VERSION 5.8 ;
BUSBITCHARS "[]" ;
DIVIDERCHAR "/" ;
UNITS
    DATABASE MICRONS 1000 ;
END UNITS

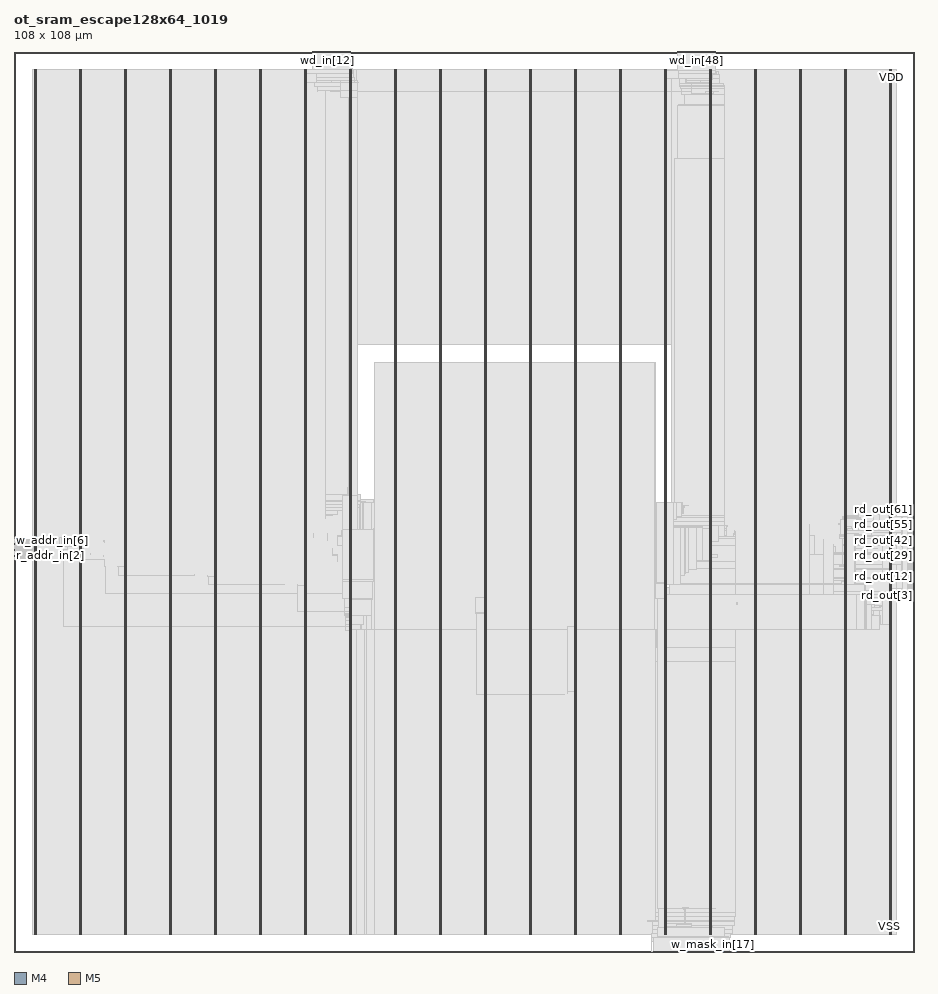
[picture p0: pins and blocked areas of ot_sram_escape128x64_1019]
MACRO ot_sram_escape128x64_1019
  FOREIGN ot_sram_escape128x64_1019 0 0 ;
  CLASS BLOCK ;
  SIZE 108 BY 108 ;
  PIN clk
    DIRECTION INPUT ;
    USE SIGNAL ;
    PORT
      LAYER M4 ;
        RECT  0 47.088 0.084 47.112 ;
    END
  END clk
  PIN r_addr_in[0]
    DIRECTION INPUT ;
    USE SIGNAL ;
    PORT
      LAYER M4 ;
        RECT  0 47.232 0.084 47.256 ;
    END
  END r_addr_in[0]
  PIN r_addr_in[1]
    DIRECTION INPUT ;
    USE SIGNAL ;
    PORT
      LAYER M4 ;
        RECT  0 47.376 0.084 47.4 ;
    END
  END r_addr_in[1]
  PIN r_addr_in[2]
    DIRECTION INPUT ;
    USE SIGNAL ;
    PORT
      LAYER M4 ;
        RECT  0 47.52 0.084 47.544 ;
    END
  END r_addr_in[2]
  PIN r_addr_in[3]
    DIRECTION INPUT ;
    USE SIGNAL ;
    PORT
      LAYER M4 ;
        RECT  0 47.664 0.084 47.688 ;
    END
  END r_addr_in[3]
  PIN r_addr_in[4]
    DIRECTION INPUT ;
    USE SIGNAL ;
    PORT
      LAYER M4 ;
        RECT  0 47.808 0.084 47.832 ;
    END
  END r_addr_in[4]
  PIN r_addr_in[5]
    DIRECTION INPUT ;
    USE SIGNAL ;
    PORT
      LAYER M4 ;
        RECT  0 47.952 0.084 47.976 ;
    END
  END r_addr_in[5]
  PIN r_addr_in[6]
    DIRECTION INPUT ;
    USE SIGNAL ;
    PORT
      LAYER M4 ;
        RECT  0 48.096 0.084 48.12 ;
    END
  END r_addr_in[6]
  PIN r_ce_in
    DIRECTION INPUT ;
    USE SIGNAL ;
    PORT
      LAYER M4 ;
        RECT  0 48.24 0.084 48.264 ;
    END
  END r_ce_in
  PIN rd_out[0]
    DIRECTION OUTPUT ;
    USE SIGNAL ;
    PORT
      LAYER M4 ;
        RECT  107.916 43.344 108 43.368 ;
    END
  END rd_out[0]
  PIN rd_out[10]
    DIRECTION OUTPUT ;
    USE SIGNAL ;
    PORT
      LAYER M4 ;
        RECT  107.916 44.784 108 44.808 ;
    END
  END rd_out[10]
  PIN rd_out[11]
    DIRECTION OUTPUT ;
    USE SIGNAL ;
    PORT
      LAYER M4 ;
        RECT  107.916 44.928 108 44.952 ;
    END
  END rd_out[11]
  PIN rd_out[12]
    DIRECTION OUTPUT ;
    USE SIGNAL ;
    PORT
      LAYER M4 ;
        RECT  107.916 45.072 108 45.096 ;
    END
  END rd_out[12]
  PIN rd_out[13]
    DIRECTION OUTPUT ;
    USE SIGNAL ;
    PORT
      LAYER M4 ;
        RECT  107.916 45.216 108 45.24 ;
    END
  END rd_out[13]
  PIN rd_out[14]
    DIRECTION OUTPUT ;
    USE SIGNAL ;
    PORT
      LAYER M4 ;
        RECT  107.916 45.36 108 45.384 ;
    END
  END rd_out[14]
  PIN rd_out[15]
    DIRECTION OUTPUT ;
    USE SIGNAL ;
    PORT
      LAYER M4 ;
        RECT  107.916 45.504 108 45.528 ;
    END
  END rd_out[15]
  PIN rd_out[16]
    DIRECTION OUTPUT ;
    USE SIGNAL ;
    PORT
      LAYER M4 ;
        RECT  107.916 45.648 108 45.672 ;
    END
  END rd_out[16]
  PIN rd_out[17]
    DIRECTION OUTPUT ;
    USE SIGNAL ;
    PORT
      LAYER M4 ;
        RECT  107.916 45.792 108 45.816 ;
    END
  END rd_out[17]
  PIN rd_out[18]
    DIRECTION OUTPUT ;
    USE SIGNAL ;
    PORT
      LAYER M4 ;
        RECT  107.916 45.936 108 45.96 ;
    END
  END rd_out[18]
  PIN rd_out[19]
    DIRECTION OUTPUT ;
    USE SIGNAL ;
    PORT
      LAYER M4 ;
        RECT  107.916 46.08 108 46.104 ;
    END
  END rd_out[19]
  PIN rd_out[1]
    DIRECTION OUTPUT ;
    USE SIGNAL ;
    PORT
      LAYER M4 ;
        RECT  107.916 43.488 108 43.512 ;
    END
  END rd_out[1]
  PIN rd_out[20]
    DIRECTION OUTPUT ;
    USE SIGNAL ;
    PORT
      LAYER M4 ;
        RECT  107.916 46.224 108 46.248 ;
    END
  END rd_out[20]
  PIN rd_out[21]
    DIRECTION OUTPUT ;
    USE SIGNAL ;
    PORT
      LAYER M4 ;
        RECT  107.916 46.368 108 46.392 ;
    END
  END rd_out[21]
  PIN rd_out[22]
    DIRECTION OUTPUT ;
    USE SIGNAL ;
    PORT
      LAYER M4 ;
        RECT  107.916 46.512 108 46.536 ;
    END
  END rd_out[22]
  PIN rd_out[23]
    DIRECTION OUTPUT ;
    USE SIGNAL ;
    PORT
      LAYER M4 ;
        RECT  107.916 46.656 108 46.68 ;
    END
  END rd_out[23]
  PIN rd_out[24]
    DIRECTION OUTPUT ;
    USE SIGNAL ;
    PORT
      LAYER M4 ;
        RECT  107.916 46.8 108 46.824 ;
    END
  END rd_out[24]
  PIN rd_out[25]
    DIRECTION OUTPUT ;
    USE SIGNAL ;
    PORT
      LAYER M4 ;
        RECT  107.916 46.944 108 46.968 ;
    END
  END rd_out[25]
  PIN rd_out[26]
    DIRECTION OUTPUT ;
    USE SIGNAL ;
    PORT
      LAYER M4 ;
        RECT  107.916 47.088 108 47.112 ;
    END
  END rd_out[26]
  PIN rd_out[27]
    DIRECTION OUTPUT ;
    USE SIGNAL ;
    PORT
      LAYER M4 ;
        RECT  107.916 47.232 108 47.256 ;
    END
  END rd_out[27]
  PIN rd_out[28]
    DIRECTION OUTPUT ;
    USE SIGNAL ;
    PORT
      LAYER M4 ;
        RECT  107.916 47.376 108 47.4 ;
    END
  END rd_out[28]
  PIN rd_out[29]
    DIRECTION OUTPUT ;
    USE SIGNAL ;
    PORT
      LAYER M4 ;
        RECT  107.916 47.52 108 47.544 ;
    END
  END rd_out[29]
  PIN rd_out[2]
    DIRECTION OUTPUT ;
    USE SIGNAL ;
    PORT
      LAYER M4 ;
        RECT  107.916 43.632 108 43.656 ;
    END
  END rd_out[2]
  PIN rd_out[30]
    DIRECTION OUTPUT ;
    USE SIGNAL ;
    PORT
      LAYER M4 ;
        RECT  107.916 47.664 108 47.688 ;
    END
  END rd_out[30]
  PIN rd_out[31]
    DIRECTION OUTPUT ;
    USE SIGNAL ;
    PORT
      LAYER M4 ;
        RECT  107.916 47.808 108 47.832 ;
    END
  END rd_out[31]
  PIN rd_out[32]
    DIRECTION OUTPUT ;
    USE SIGNAL ;
    PORT
      LAYER M4 ;
        RECT  107.916 47.952 108 47.976 ;
    END
  END rd_out[32]
  PIN rd_out[33]
    DIRECTION OUTPUT ;
    USE SIGNAL ;
    PORT
      LAYER M4 ;
        RECT  107.916 48.096 108 48.12 ;
    END
  END rd_out[33]
  PIN rd_out[34]
    DIRECTION OUTPUT ;
    USE SIGNAL ;
    PORT
      LAYER M4 ;
        RECT  107.916 48.24 108 48.264 ;
    END
  END rd_out[34]
  PIN rd_out[35]
    DIRECTION OUTPUT ;
    USE SIGNAL ;
    PORT
      LAYER M4 ;
        RECT  107.916 48.384 108 48.408 ;
    END
  END rd_out[35]
  PIN rd_out[36]
    DIRECTION OUTPUT ;
    USE SIGNAL ;
    PORT
      LAYER M4 ;
        RECT  107.916 48.528 108 48.552 ;
    END
  END rd_out[36]
  PIN rd_out[37]
    DIRECTION OUTPUT ;
    USE SIGNAL ;
    PORT
      LAYER M4 ;
        RECT  107.916 48.672 108 48.696 ;
    END
  END rd_out[37]
  PIN rd_out[38]
    DIRECTION OUTPUT ;
    USE SIGNAL ;
    PORT
      LAYER M4 ;
        RECT  107.916 48.816 108 48.84 ;
    END
  END rd_out[38]
  PIN rd_out[39]
    DIRECTION OUTPUT ;
    USE SIGNAL ;
    PORT
      LAYER M4 ;
        RECT  107.916 48.96 108 48.984 ;
    END
  END rd_out[39]
  PIN rd_out[3]
    DIRECTION OUTPUT ;
    USE SIGNAL ;
    PORT
      LAYER M4 ;
        RECT  107.916 43.776 108 43.8 ;
    END
  END rd_out[3]
  PIN rd_out[40]
    DIRECTION OUTPUT ;
    USE SIGNAL ;
    PORT
      LAYER M4 ;
        RECT  107.916 49.104 108 49.128 ;
    END
  END rd_out[40]
  PIN rd_out[41]
    DIRECTION OUTPUT ;
    USE SIGNAL ;
    PORT
      LAYER M4 ;
        RECT  107.916 49.248 108 49.272 ;
    END
  END rd_out[41]
  PIN rd_out[42]
    DIRECTION OUTPUT ;
    USE SIGNAL ;
    PORT
      LAYER M4 ;
        RECT  107.916 49.392 108 49.416 ;
    END
  END rd_out[42]
  PIN rd_out[43]
    DIRECTION OUTPUT ;
    USE SIGNAL ;
    PORT
      LAYER M4 ;
        RECT  107.916 49.536 108 49.56 ;
    END
  END rd_out[43]
  PIN rd_out[44]
    DIRECTION OUTPUT ;
    USE SIGNAL ;
    PORT
      LAYER M4 ;
        RECT  107.916 49.68 108 49.704 ;
    END
  END rd_out[44]
  PIN rd_out[45]
    DIRECTION OUTPUT ;
    USE SIGNAL ;
    PORT
      LAYER M4 ;
        RECT  107.916 49.824 108 49.848 ;
    END
  END rd_out[45]
  PIN rd_out[46]
    DIRECTION OUTPUT ;
    USE SIGNAL ;
    PORT
      LAYER M4 ;
        RECT  107.916 49.968 108 49.992 ;
    END
  END rd_out[46]
  PIN rd_out[47]
    DIRECTION OUTPUT ;
    USE SIGNAL ;
    PORT
      LAYER M4 ;
        RECT  107.916 50.112 108 50.136 ;
    END
  END rd_out[47]
  PIN rd_out[48]
    DIRECTION OUTPUT ;
    USE SIGNAL ;
    PORT
      LAYER M4 ;
        RECT  107.916 50.256 108 50.28 ;
    END
  END rd_out[48]
  PIN rd_out[49]
    DIRECTION OUTPUT ;
    USE SIGNAL ;
    PORT
      LAYER M4 ;
        RECT  107.916 50.4 108 50.424 ;
    END
  END rd_out[49]
  PIN rd_out[4]
    DIRECTION OUTPUT ;
    USE SIGNAL ;
    PORT
      LAYER M4 ;
        RECT  107.916 43.92 108 43.944 ;
    END
  END rd_out[4]
  PIN rd_out[50]
    DIRECTION OUTPUT ;
    USE SIGNAL ;
    PORT
      LAYER M4 ;
        RECT  107.916 50.544 108 50.568 ;
    END
  END rd_out[50]
  PIN rd_out[51]
    DIRECTION OUTPUT ;
    USE SIGNAL ;
    PORT
      LAYER M4 ;
        RECT  107.916 50.688 108 50.712 ;
    END
  END rd_out[51]
  PIN rd_out[52]
    DIRECTION OUTPUT ;
    USE SIGNAL ;
    PORT
      LAYER M4 ;
        RECT  107.916 50.832 108 50.856 ;
    END
  END rd_out[52]
  PIN rd_out[53]
    DIRECTION OUTPUT ;
    USE SIGNAL ;
    PORT
      LAYER M4 ;
        RECT  107.916 50.976 108 51 ;
    END
  END rd_out[53]
  PIN rd_out[54]
    DIRECTION OUTPUT ;
    USE SIGNAL ;
    PORT
      LAYER M4 ;
        RECT  107.916 51.12 108 51.144 ;
    END
  END rd_out[54]
  PIN rd_out[55]
    DIRECTION OUTPUT ;
    USE SIGNAL ;
    PORT
      LAYER M4 ;
        RECT  107.916 51.264 108 51.288 ;
    END
  END rd_out[55]
  PIN rd_out[56]
    DIRECTION OUTPUT ;
    USE SIGNAL ;
    PORT
      LAYER M4 ;
        RECT  107.916 51.408 108 51.432 ;
    END
  END rd_out[56]
  PIN rd_out[57]
    DIRECTION OUTPUT ;
    USE SIGNAL ;
    PORT
      LAYER M4 ;
        RECT  107.916 51.552 108 51.576 ;
    END
  END rd_out[57]
  PIN rd_out[58]
    DIRECTION OUTPUT ;
    USE SIGNAL ;
    PORT
      LAYER M4 ;
        RECT  107.916 51.696 108 51.72 ;
    END
  END rd_out[58]
  PIN rd_out[59]
    DIRECTION OUTPUT ;
    USE SIGNAL ;
    PORT
      LAYER M4 ;
        RECT  107.916 51.84 108 51.864 ;
    END
  END rd_out[59]
  PIN rd_out[5]
    DIRECTION OUTPUT ;
    USE SIGNAL ;
    PORT
      LAYER M4 ;
        RECT  107.916 44.064 108 44.088 ;
    END
  END rd_out[5]
  PIN rd_out[60]
    DIRECTION OUTPUT ;
    USE SIGNAL ;
    PORT
      LAYER M4 ;
        RECT  107.916 51.984 108 52.008 ;
    END
  END rd_out[60]
  PIN rd_out[61]
    DIRECTION OUTPUT ;
    USE SIGNAL ;
    PORT
      LAYER M4 ;
        RECT  107.916 52.128 108 52.152 ;
    END
  END rd_out[61]
  PIN rd_out[62]
    DIRECTION OUTPUT ;
    USE SIGNAL ;
    PORT
      LAYER M4 ;
        RECT  107.916 52.272 108 52.296 ;
    END
  END rd_out[62]
  PIN rd_out[63]
    DIRECTION OUTPUT ;
    USE SIGNAL ;
    PORT
      LAYER M4 ;
        RECT  107.916 52.416 108 52.44 ;
    END
  END rd_out[63]
  PIN rd_out[6]
    DIRECTION OUTPUT ;
    USE SIGNAL ;
    PORT
      LAYER M4 ;
        RECT  107.916 44.208 108 44.232 ;
    END
  END rd_out[6]
  PIN rd_out[7]
    DIRECTION OUTPUT ;
    USE SIGNAL ;
    PORT
      LAYER M4 ;
        RECT  107.916 44.352 108 44.376 ;
    END
  END rd_out[7]
  PIN rd_out[8]
    DIRECTION OUTPUT ;
    USE SIGNAL ;
    PORT
      LAYER M4 ;
        RECT  107.916 44.496 108 44.52 ;
    END
  END rd_out[8]
  PIN rd_out[9]
    DIRECTION OUTPUT ;
    USE SIGNAL ;
    PORT
      LAYER M4 ;
        RECT  107.916 44.64 108 44.664 ;
    END
  END rd_out[9]
  PIN rst_n
    DIRECTION INPUT ;
    USE SIGNAL ;
    PORT
      LAYER M4 ;
        RECT  0 48.384 0.084 48.408 ;
    END
  END rst_n
  PIN w_addr_in[0]
    DIRECTION INPUT ;
    USE SIGNAL ;
    PORT
      LAYER M4 ;
        RECT  0 48.528 0.084 48.552 ;
    END
  END w_addr_in[0]
  PIN w_addr_in[1]
    DIRECTION INPUT ;
    USE SIGNAL ;
    PORT
      LAYER M4 ;
        RECT  0 48.672 0.084 48.696 ;
    END
  END w_addr_in[1]
  PIN w_addr_in[2]
    DIRECTION INPUT ;
    USE SIGNAL ;
    PORT
      LAYER M4 ;
        RECT  0 48.816 0.084 48.84 ;
    END
  END w_addr_in[2]
  PIN w_addr_in[3]
    DIRECTION INPUT ;
    USE SIGNAL ;
    PORT
      LAYER M4 ;
        RECT  0 48.96 0.084 48.984 ;
    END
  END w_addr_in[3]
  PIN w_addr_in[4]
    DIRECTION INPUT ;
    USE SIGNAL ;
    PORT
      LAYER M4 ;
        RECT  0 49.104 0.084 49.128 ;
    END
  END w_addr_in[4]
  PIN w_addr_in[5]
    DIRECTION INPUT ;
    USE SIGNAL ;
    PORT
      LAYER M4 ;
        RECT  0 49.248 0.084 49.272 ;
    END
  END w_addr_in[5]
  PIN w_addr_in[6]
    DIRECTION INPUT ;
    USE SIGNAL ;
    PORT
      LAYER M4 ;
        RECT  0 49.392 0.084 49.416 ;
    END
  END w_addr_in[6]
  PIN w_ce_in
    DIRECTION INPUT ;
    USE SIGNAL ;
    PORT
      LAYER M4 ;
        RECT  0 49.536 0.084 49.56 ;
    END
  END w_ce_in
  PIN w_mask_in[0]
    DIRECTION INPUT ;
    USE SIGNAL ;
    PORT
      LAYER M5 ;
        RECT  81.36 0 81.384 0.084 ;
    END
  END w_mask_in[0]
  PIN w_mask_in[10]
    DIRECTION INPUT ;
    USE SIGNAL ;
    PORT
      LAYER M5 ;
        RECT  82.8 0 82.824 0.084 ;
    END
  END w_mask_in[10]
  PIN w_mask_in[11]
    DIRECTION INPUT ;
    USE SIGNAL ;
    PORT
      LAYER M5 ;
        RECT  82.944 0 82.968 0.084 ;
    END
  END w_mask_in[11]
  PIN w_mask_in[12]
    DIRECTION INPUT ;
    USE SIGNAL ;
    PORT
      LAYER M5 ;
        RECT  83.088 0 83.112 0.084 ;
    END
  END w_mask_in[12]
  PIN w_mask_in[13]
    DIRECTION INPUT ;
    USE SIGNAL ;
    PORT
      LAYER M5 ;
        RECT  83.232 0 83.256 0.084 ;
    END
  END w_mask_in[13]
  PIN w_mask_in[14]
    DIRECTION INPUT ;
    USE SIGNAL ;
    PORT
      LAYER M5 ;
        RECT  83.376 0 83.4 0.084 ;
    END
  END w_mask_in[14]
  PIN w_mask_in[15]
    DIRECTION INPUT ;
    USE SIGNAL ;
    PORT
      LAYER M5 ;
        RECT  83.52 0 83.544 0.084 ;
    END
  END w_mask_in[15]
  PIN w_mask_in[16]
    DIRECTION INPUT ;
    USE SIGNAL ;
    PORT
      LAYER M5 ;
        RECT  83.664 0 83.688 0.084 ;
    END
  END w_mask_in[16]
  PIN w_mask_in[17]
    DIRECTION INPUT ;
    USE SIGNAL ;
    PORT
      LAYER M5 ;
        RECT  83.808 0 83.832 0.084 ;
    END
  END w_mask_in[17]
  PIN w_mask_in[18]
    DIRECTION INPUT ;
    USE SIGNAL ;
    PORT
      LAYER M5 ;
        RECT  83.952 0 83.976 0.084 ;
    END
  END w_mask_in[18]
  PIN w_mask_in[19]
    DIRECTION INPUT ;
    USE SIGNAL ;
    PORT
      LAYER M5 ;
        RECT  84.096 0 84.12 0.084 ;
    END
  END w_mask_in[19]
  PIN w_mask_in[1]
    DIRECTION INPUT ;
    USE SIGNAL ;
    PORT
      LAYER M5 ;
        RECT  81.504 0 81.528 0.084 ;
    END
  END w_mask_in[1]
  PIN w_mask_in[20]
    DIRECTION INPUT ;
    USE SIGNAL ;
    PORT
      LAYER M5 ;
        RECT  84.24 0 84.264 0.084 ;
    END
  END w_mask_in[20]
  PIN w_mask_in[21]
    DIRECTION INPUT ;
    USE SIGNAL ;
    PORT
      LAYER M5 ;
        RECT  84.384 0 84.408 0.084 ;
    END
  END w_mask_in[21]
  PIN w_mask_in[22]
    DIRECTION INPUT ;
    USE SIGNAL ;
    PORT
      LAYER M5 ;
        RECT  84.528 0 84.552 0.084 ;
    END
  END w_mask_in[22]
  PIN w_mask_in[23]
    DIRECTION INPUT ;
    USE SIGNAL ;
    PORT
      LAYER M5 ;
        RECT  84.672 0 84.696 0.084 ;
    END
  END w_mask_in[23]
  PIN w_mask_in[24]
    DIRECTION INPUT ;
    USE SIGNAL ;
    PORT
      LAYER M5 ;
        RECT  84.816 0 84.84 0.084 ;
    END
  END w_mask_in[24]
  PIN w_mask_in[25]
    DIRECTION INPUT ;
    USE SIGNAL ;
    PORT
      LAYER M5 ;
        RECT  84.96 0 84.984 0.084 ;
    END
  END w_mask_in[25]
  PIN w_mask_in[26]
    DIRECTION INPUT ;
    USE SIGNAL ;
    PORT
      LAYER M5 ;
        RECT  85.104 0 85.128 0.084 ;
    END
  END w_mask_in[26]
  PIN w_mask_in[27]
    DIRECTION INPUT ;
    USE SIGNAL ;
    PORT
      LAYER M5 ;
        RECT  85.248 0 85.272 0.084 ;
    END
  END w_mask_in[27]
  PIN w_mask_in[28]
    DIRECTION INPUT ;
    USE SIGNAL ;
    PORT
      LAYER M5 ;
        RECT  85.392 0 85.416 0.084 ;
    END
  END w_mask_in[28]
  PIN w_mask_in[29]
    DIRECTION INPUT ;
    USE SIGNAL ;
    PORT
      LAYER M5 ;
        RECT  85.536 0 85.56 0.084 ;
    END
  END w_mask_in[29]
  PIN w_mask_in[2]
    DIRECTION INPUT ;
    USE SIGNAL ;
    PORT
      LAYER M5 ;
        RECT  81.648 0 81.672 0.084 ;
    END
  END w_mask_in[2]
  PIN w_mask_in[30]
    DIRECTION INPUT ;
    USE SIGNAL ;
    PORT
      LAYER M5 ;
        RECT  85.68 0 85.704 0.084 ;
    END
  END w_mask_in[30]
  PIN w_mask_in[31]
    DIRECTION INPUT ;
    USE SIGNAL ;
    PORT
      LAYER M5 ;
        RECT  85.824 0 85.848 0.084 ;
    END
  END w_mask_in[31]
  PIN w_mask_in[32]
    DIRECTION INPUT ;
    USE SIGNAL ;
    PORT
      LAYER M5 ;
        RECT  76.752 0 76.776 0.084 ;
    END
  END w_mask_in[32]
  PIN w_mask_in[33]
    DIRECTION INPUT ;
    USE SIGNAL ;
    PORT
      LAYER M5 ;
        RECT  76.896 0 76.92 0.084 ;
    END
  END w_mask_in[33]
  PIN w_mask_in[34]
    DIRECTION INPUT ;
    USE SIGNAL ;
    PORT
      LAYER M5 ;
        RECT  77.04 0 77.064 0.084 ;
    END
  END w_mask_in[34]
  PIN w_mask_in[35]
    DIRECTION INPUT ;
    USE SIGNAL ;
    PORT
      LAYER M5 ;
        RECT  77.184 0 77.208 0.084 ;
    END
  END w_mask_in[35]
  PIN w_mask_in[36]
    DIRECTION INPUT ;
    USE SIGNAL ;
    PORT
      LAYER M5 ;
        RECT  77.328 0 77.352 0.084 ;
    END
  END w_mask_in[36]
  PIN w_mask_in[37]
    DIRECTION INPUT ;
    USE SIGNAL ;
    PORT
      LAYER M5 ;
        RECT  77.472 0 77.496 0.084 ;
    END
  END w_mask_in[37]
  PIN w_mask_in[38]
    DIRECTION INPUT ;
    USE SIGNAL ;
    PORT
      LAYER M5 ;
        RECT  77.616 0 77.64 0.084 ;
    END
  END w_mask_in[38]
  PIN w_mask_in[39]
    DIRECTION INPUT ;
    USE SIGNAL ;
    PORT
      LAYER M5 ;
        RECT  77.76 0 77.784 0.084 ;
    END
  END w_mask_in[39]
  PIN w_mask_in[3]
    DIRECTION INPUT ;
    USE SIGNAL ;
    PORT
      LAYER M5 ;
        RECT  81.792 0 81.816 0.084 ;
    END
  END w_mask_in[3]
  PIN w_mask_in[40]
    DIRECTION INPUT ;
    USE SIGNAL ;
    PORT
      LAYER M5 ;
        RECT  77.904 0 77.928 0.084 ;
    END
  END w_mask_in[40]
  PIN w_mask_in[41]
    DIRECTION INPUT ;
    USE SIGNAL ;
    PORT
      LAYER M5 ;
        RECT  78.048 0 78.072 0.084 ;
    END
  END w_mask_in[41]
  PIN w_mask_in[42]
    DIRECTION INPUT ;
    USE SIGNAL ;
    PORT
      LAYER M5 ;
        RECT  78.192 0 78.216 0.084 ;
    END
  END w_mask_in[42]
  PIN w_mask_in[43]
    DIRECTION INPUT ;
    USE SIGNAL ;
    PORT
      LAYER M5 ;
        RECT  78.336 0 78.36 0.084 ;
    END
  END w_mask_in[43]
  PIN w_mask_in[44]
    DIRECTION INPUT ;
    USE SIGNAL ;
    PORT
      LAYER M5 ;
        RECT  78.48 0 78.504 0.084 ;
    END
  END w_mask_in[44]
  PIN w_mask_in[45]
    DIRECTION INPUT ;
    USE SIGNAL ;
    PORT
      LAYER M5 ;
        RECT  78.624 0 78.648 0.084 ;
    END
  END w_mask_in[45]
  PIN w_mask_in[46]
    DIRECTION INPUT ;
    USE SIGNAL ;
    PORT
      LAYER M5 ;
        RECT  78.768 0 78.792 0.084 ;
    END
  END w_mask_in[46]
  PIN w_mask_in[47]
    DIRECTION INPUT ;
    USE SIGNAL ;
    PORT
      LAYER M5 ;
        RECT  78.912 0 78.936 0.084 ;
    END
  END w_mask_in[47]
  PIN w_mask_in[48]
    DIRECTION INPUT ;
    USE SIGNAL ;
    PORT
      LAYER M5 ;
        RECT  79.056 0 79.08 0.084 ;
    END
  END w_mask_in[48]
  PIN w_mask_in[49]
    DIRECTION INPUT ;
    USE SIGNAL ;
    PORT
      LAYER M5 ;
        RECT  79.2 0 79.224 0.084 ;
    END
  END w_mask_in[49]
  PIN w_mask_in[4]
    DIRECTION INPUT ;
    USE SIGNAL ;
    PORT
      LAYER M5 ;
        RECT  81.936 0 81.96 0.084 ;
    END
  END w_mask_in[4]
  PIN w_mask_in[50]
    DIRECTION INPUT ;
    USE SIGNAL ;
    PORT
      LAYER M5 ;
        RECT  79.344 0 79.368 0.084 ;
    END
  END w_mask_in[50]
  PIN w_mask_in[51]
    DIRECTION INPUT ;
    USE SIGNAL ;
    PORT
      LAYER M5 ;
        RECT  79.488 0 79.512 0.084 ;
    END
  END w_mask_in[51]
  PIN w_mask_in[52]
    DIRECTION INPUT ;
    USE SIGNAL ;
    PORT
      LAYER M5 ;
        RECT  79.632 0 79.656 0.084 ;
    END
  END w_mask_in[52]
  PIN w_mask_in[53]
    DIRECTION INPUT ;
    USE SIGNAL ;
    PORT
      LAYER M5 ;
        RECT  79.776 0 79.8 0.084 ;
    END
  END w_mask_in[53]
  PIN w_mask_in[54]
    DIRECTION INPUT ;
    USE SIGNAL ;
    PORT
      LAYER M5 ;
        RECT  79.92 0 79.944 0.084 ;
    END
  END w_mask_in[54]
  PIN w_mask_in[55]
    DIRECTION INPUT ;
    USE SIGNAL ;
    PORT
      LAYER M5 ;
        RECT  80.064 0 80.088 0.084 ;
    END
  END w_mask_in[55]
  PIN w_mask_in[56]
    DIRECTION INPUT ;
    USE SIGNAL ;
    PORT
      LAYER M5 ;
        RECT  80.208 0 80.232 0.084 ;
    END
  END w_mask_in[56]
  PIN w_mask_in[57]
    DIRECTION INPUT ;
    USE SIGNAL ;
    PORT
      LAYER M5 ;
        RECT  80.352 0 80.376 0.084 ;
    END
  END w_mask_in[57]
  PIN w_mask_in[58]
    DIRECTION INPUT ;
    USE SIGNAL ;
    PORT
      LAYER M5 ;
        RECT  80.496 0 80.52 0.084 ;
    END
  END w_mask_in[58]
  PIN w_mask_in[59]
    DIRECTION INPUT ;
    USE SIGNAL ;
    PORT
      LAYER M5 ;
        RECT  80.64 0 80.664 0.084 ;
    END
  END w_mask_in[59]
  PIN w_mask_in[5]
    DIRECTION INPUT ;
    USE SIGNAL ;
    PORT
      LAYER M5 ;
        RECT  82.08 0 82.104 0.084 ;
    END
  END w_mask_in[5]
  PIN w_mask_in[60]
    DIRECTION INPUT ;
    USE SIGNAL ;
    PORT
      LAYER M5 ;
        RECT  80.784 0 80.808 0.084 ;
    END
  END w_mask_in[60]
  PIN w_mask_in[61]
    DIRECTION INPUT ;
    USE SIGNAL ;
    PORT
      LAYER M5 ;
        RECT  80.928 0 80.952 0.084 ;
    END
  END w_mask_in[61]
  PIN w_mask_in[62]
    DIRECTION INPUT ;
    USE SIGNAL ;
    PORT
      LAYER M5 ;
        RECT  81.072 0 81.096 0.084 ;
    END
  END w_mask_in[62]
  PIN w_mask_in[63]
    DIRECTION INPUT ;
    USE SIGNAL ;
    PORT
      LAYER M5 ;
        RECT  81.216 0 81.24 0.084 ;
    END
  END w_mask_in[63]
  PIN w_mask_in[6]
    DIRECTION INPUT ;
    USE SIGNAL ;
    PORT
      LAYER M5 ;
        RECT  82.224 0 82.248 0.084 ;
    END
  END w_mask_in[6]
  PIN w_mask_in[7]
    DIRECTION INPUT ;
    USE SIGNAL ;
    PORT
      LAYER M5 ;
        RECT  82.368 0 82.392 0.084 ;
    END
  END w_mask_in[7]
  PIN w_mask_in[8]
    DIRECTION INPUT ;
    USE SIGNAL ;
    PORT
      LAYER M5 ;
        RECT  82.512 0 82.536 0.084 ;
    END
  END w_mask_in[8]
  PIN w_mask_in[9]
    DIRECTION INPUT ;
    USE SIGNAL ;
    PORT
      LAYER M5 ;
        RECT  82.656 0 82.68 0.084 ;
    END
  END w_mask_in[9]
  PIN wd_in[0]
    DIRECTION INPUT ;
    USE SIGNAL ;
    PORT
      LAYER M5 ;
        RECT  35.856 107.916 35.88 108 ;
    END
  END wd_in[0]
  PIN wd_in[10]
    DIRECTION INPUT ;
    USE SIGNAL ;
    PORT
      LAYER M5 ;
        RECT  37.296 107.916 37.32 108 ;
    END
  END wd_in[10]
  PIN wd_in[11]
    DIRECTION INPUT ;
    USE SIGNAL ;
    PORT
      LAYER M5 ;
        RECT  37.44 107.916 37.464 108 ;
    END
  END wd_in[11]
  PIN wd_in[12]
    DIRECTION INPUT ;
    USE SIGNAL ;
    PORT
      LAYER M5 ;
        RECT  37.584 107.916 37.608 108 ;
    END
  END wd_in[12]
  PIN wd_in[13]
    DIRECTION INPUT ;
    USE SIGNAL ;
    PORT
      LAYER M5 ;
        RECT  37.728 107.916 37.752 108 ;
    END
  END wd_in[13]
  PIN wd_in[14]
    DIRECTION INPUT ;
    USE SIGNAL ;
    PORT
      LAYER M5 ;
        RECT  37.872 107.916 37.896 108 ;
    END
  END wd_in[14]
  PIN wd_in[15]
    DIRECTION INPUT ;
    USE SIGNAL ;
    PORT
      LAYER M5 ;
        RECT  38.016 107.916 38.04 108 ;
    END
  END wd_in[15]
  PIN wd_in[16]
    DIRECTION INPUT ;
    USE SIGNAL ;
    PORT
      LAYER M5 ;
        RECT  38.16 107.916 38.184 108 ;
    END
  END wd_in[16]
  PIN wd_in[17]
    DIRECTION INPUT ;
    USE SIGNAL ;
    PORT
      LAYER M5 ;
        RECT  38.304 107.916 38.328 108 ;
    END
  END wd_in[17]
  PIN wd_in[18]
    DIRECTION INPUT ;
    USE SIGNAL ;
    PORT
      LAYER M5 ;
        RECT  38.448 107.916 38.472 108 ;
    END
  END wd_in[18]
  PIN wd_in[19]
    DIRECTION INPUT ;
    USE SIGNAL ;
    PORT
      LAYER M5 ;
        RECT  38.592 107.916 38.616 108 ;
    END
  END wd_in[19]
  PIN wd_in[1]
    DIRECTION INPUT ;
    USE SIGNAL ;
    PORT
      LAYER M5 ;
        RECT  36 107.916 36.024 108 ;
    END
  END wd_in[1]
  PIN wd_in[20]
    DIRECTION INPUT ;
    USE SIGNAL ;
    PORT
      LAYER M5 ;
        RECT  38.736 107.916 38.76 108 ;
    END
  END wd_in[20]
  PIN wd_in[21]
    DIRECTION INPUT ;
    USE SIGNAL ;
    PORT
      LAYER M5 ;
        RECT  38.88 107.916 38.904 108 ;
    END
  END wd_in[21]
  PIN wd_in[22]
    DIRECTION INPUT ;
    USE SIGNAL ;
    PORT
      LAYER M5 ;
        RECT  39.024 107.916 39.048 108 ;
    END
  END wd_in[22]
  PIN wd_in[23]
    DIRECTION INPUT ;
    USE SIGNAL ;
    PORT
      LAYER M5 ;
        RECT  39.168 107.916 39.192 108 ;
    END
  END wd_in[23]
  PIN wd_in[24]
    DIRECTION INPUT ;
    USE SIGNAL ;
    PORT
      LAYER M5 ;
        RECT  39.312 107.916 39.336 108 ;
    END
  END wd_in[24]
  PIN wd_in[25]
    DIRECTION INPUT ;
    USE SIGNAL ;
    PORT
      LAYER M5 ;
        RECT  39.456 107.916 39.48 108 ;
    END
  END wd_in[25]
  PIN wd_in[26]
    DIRECTION INPUT ;
    USE SIGNAL ;
    PORT
      LAYER M5 ;
        RECT  39.6 107.916 39.624 108 ;
    END
  END wd_in[26]
  PIN wd_in[27]
    DIRECTION INPUT ;
    USE SIGNAL ;
    PORT
      LAYER M5 ;
        RECT  39.744 107.916 39.768 108 ;
    END
  END wd_in[27]
  PIN wd_in[28]
    DIRECTION INPUT ;
    USE SIGNAL ;
    PORT
      LAYER M5 ;
        RECT  39.888 107.916 39.912 108 ;
    END
  END wd_in[28]
  PIN wd_in[29]
    DIRECTION INPUT ;
    USE SIGNAL ;
    PORT
      LAYER M5 ;
        RECT  40.032 107.916 40.056 108 ;
    END
  END wd_in[29]
  PIN wd_in[2]
    DIRECTION INPUT ;
    USE SIGNAL ;
    PORT
      LAYER M5 ;
        RECT  36.144 107.916 36.168 108 ;
    END
  END wd_in[2]
  PIN wd_in[30]
    DIRECTION INPUT ;
    USE SIGNAL ;
    PORT
      LAYER M5 ;
        RECT  40.176 107.916 40.2 108 ;
    END
  END wd_in[30]
  PIN wd_in[31]
    DIRECTION INPUT ;
    USE SIGNAL ;
    PORT
      LAYER M5 ;
        RECT  40.32 107.916 40.344 108 ;
    END
  END wd_in[31]
  PIN wd_in[32]
    DIRECTION INPUT ;
    USE SIGNAL ;
    PORT
      LAYER M5 ;
        RECT  79.632 107.916 79.656 108 ;
    END
  END wd_in[32]
  PIN wd_in[33]
    DIRECTION INPUT ;
    USE SIGNAL ;
    PORT
      LAYER M5 ;
        RECT  79.776 107.916 79.8 108 ;
    END
  END wd_in[33]
  PIN wd_in[34]
    DIRECTION INPUT ;
    USE SIGNAL ;
    PORT
      LAYER M5 ;
        RECT  79.92 107.916 79.944 108 ;
    END
  END wd_in[34]
  PIN wd_in[35]
    DIRECTION INPUT ;
    USE SIGNAL ;
    PORT
      LAYER M5 ;
        RECT  80.064 107.916 80.088 108 ;
    END
  END wd_in[35]
  PIN wd_in[36]
    DIRECTION INPUT ;
    USE SIGNAL ;
    PORT
      LAYER M5 ;
        RECT  80.208 107.916 80.232 108 ;
    END
  END wd_in[36]
  PIN wd_in[37]
    DIRECTION INPUT ;
    USE SIGNAL ;
    PORT
      LAYER M5 ;
        RECT  80.352 107.916 80.376 108 ;
    END
  END wd_in[37]
  PIN wd_in[38]
    DIRECTION INPUT ;
    USE SIGNAL ;
    PORT
      LAYER M5 ;
        RECT  80.496 107.916 80.52 108 ;
    END
  END wd_in[38]
  PIN wd_in[39]
    DIRECTION INPUT ;
    USE SIGNAL ;
    PORT
      LAYER M5 ;
        RECT  80.64 107.916 80.664 108 ;
    END
  END wd_in[39]
  PIN wd_in[3]
    DIRECTION INPUT ;
    USE SIGNAL ;
    PORT
      LAYER M5 ;
        RECT  36.288 107.916 36.312 108 ;
    END
  END wd_in[3]
  PIN wd_in[40]
    DIRECTION INPUT ;
    USE SIGNAL ;
    PORT
      LAYER M5 ;
        RECT  80.784 107.916 80.808 108 ;
    END
  END wd_in[40]
  PIN wd_in[41]
    DIRECTION INPUT ;
    USE SIGNAL ;
    PORT
      LAYER M5 ;
        RECT  80.928 107.916 80.952 108 ;
    END
  END wd_in[41]
  PIN wd_in[42]
    DIRECTION INPUT ;
    USE SIGNAL ;
    PORT
      LAYER M5 ;
        RECT  81.072 107.916 81.096 108 ;
    END
  END wd_in[42]
  PIN wd_in[43]
    DIRECTION INPUT ;
    USE SIGNAL ;
    PORT
      LAYER M5 ;
        RECT  81.216 107.916 81.24 108 ;
    END
  END wd_in[43]
  PIN wd_in[44]
    DIRECTION INPUT ;
    USE SIGNAL ;
    PORT
      LAYER M5 ;
        RECT  81.36 107.916 81.384 108 ;
    END
  END wd_in[44]
  PIN wd_in[45]
    DIRECTION INPUT ;
    USE SIGNAL ;
    PORT
      LAYER M5 ;
        RECT  81.504 107.916 81.528 108 ;
    END
  END wd_in[45]
  PIN wd_in[46]
    DIRECTION INPUT ;
    USE SIGNAL ;
    PORT
      LAYER M5 ;
        RECT  81.648 107.916 81.672 108 ;
    END
  END wd_in[46]
  PIN wd_in[47]
    DIRECTION INPUT ;
    USE SIGNAL ;
    PORT
      LAYER M5 ;
        RECT  81.792 107.916 81.816 108 ;
    END
  END wd_in[47]
  PIN wd_in[48]
    DIRECTION INPUT ;
    USE SIGNAL ;
    PORT
      LAYER M5 ;
        RECT  81.936 107.916 81.96 108 ;
    END
  END wd_in[48]
  PIN wd_in[49]
    DIRECTION INPUT ;
    USE SIGNAL ;
    PORT
      LAYER M5 ;
        RECT  82.08 107.916 82.104 108 ;
    END
  END wd_in[49]
  PIN wd_in[4]
    DIRECTION INPUT ;
    USE SIGNAL ;
    PORT
      LAYER M5 ;
        RECT  36.432 107.916 36.456 108 ;
    END
  END wd_in[4]
  PIN wd_in[50]
    DIRECTION INPUT ;
    USE SIGNAL ;
    PORT
      LAYER M5 ;
        RECT  82.224 107.916 82.248 108 ;
    END
  END wd_in[50]
  PIN wd_in[51]
    DIRECTION INPUT ;
    USE SIGNAL ;
    PORT
      LAYER M5 ;
        RECT  82.368 107.916 82.392 108 ;
    END
  END wd_in[51]
  PIN wd_in[52]
    DIRECTION INPUT ;
    USE SIGNAL ;
    PORT
      LAYER M5 ;
        RECT  82.512 107.916 82.536 108 ;
    END
  END wd_in[52]
  PIN wd_in[53]
    DIRECTION INPUT ;
    USE SIGNAL ;
    PORT
      LAYER M5 ;
        RECT  82.656 107.916 82.68 108 ;
    END
  END wd_in[53]
  PIN wd_in[54]
    DIRECTION INPUT ;
    USE SIGNAL ;
    PORT
      LAYER M5 ;
        RECT  82.8 107.916 82.824 108 ;
    END
  END wd_in[54]
  PIN wd_in[55]
    DIRECTION INPUT ;
    USE SIGNAL ;
    PORT
      LAYER M5 ;
        RECT  82.944 107.916 82.968 108 ;
    END
  END wd_in[55]
  PIN wd_in[56]
    DIRECTION INPUT ;
    USE SIGNAL ;
    PORT
      LAYER M5 ;
        RECT  83.088 107.916 83.112 108 ;
    END
  END wd_in[56]
  PIN wd_in[57]
    DIRECTION INPUT ;
    USE SIGNAL ;
    PORT
      LAYER M5 ;
        RECT  83.232 107.916 83.256 108 ;
    END
  END wd_in[57]
  PIN wd_in[58]
    DIRECTION INPUT ;
    USE SIGNAL ;
    PORT
      LAYER M5 ;
        RECT  83.376 107.916 83.4 108 ;
    END
  END wd_in[58]
  PIN wd_in[59]
    DIRECTION INPUT ;
    USE SIGNAL ;
    PORT
      LAYER M5 ;
        RECT  83.52 107.916 83.544 108 ;
    END
  END wd_in[59]
  PIN wd_in[5]
    DIRECTION INPUT ;
    USE SIGNAL ;
    PORT
      LAYER M5 ;
        RECT  36.576 107.916 36.6 108 ;
    END
  END wd_in[5]
  PIN wd_in[60]
    DIRECTION INPUT ;
    USE SIGNAL ;
    PORT
      LAYER M5 ;
        RECT  83.664 107.916 83.688 108 ;
    END
  END wd_in[60]
  PIN wd_in[61]
    DIRECTION INPUT ;
    USE SIGNAL ;
    PORT
      LAYER M5 ;
        RECT  83.808 107.916 83.832 108 ;
    END
  END wd_in[61]
  PIN wd_in[62]
    DIRECTION INPUT ;
    USE SIGNAL ;
    PORT
      LAYER M5 ;
        RECT  83.952 107.916 83.976 108 ;
    END
  END wd_in[62]
  PIN wd_in[63]
    DIRECTION INPUT ;
    USE SIGNAL ;
    PORT
      LAYER M5 ;
        RECT  84.096 107.916 84.12 108 ;
    END
  END wd_in[63]
  PIN wd_in[6]
    DIRECTION INPUT ;
    USE SIGNAL ;
    PORT
      LAYER M5 ;
        RECT  36.72 107.916 36.744 108 ;
    END
  END wd_in[6]
  PIN wd_in[7]
    DIRECTION INPUT ;
    USE SIGNAL ;
    PORT
      LAYER M5 ;
        RECT  36.864 107.916 36.888 108 ;
    END
  END wd_in[7]
  PIN wd_in[8]
    DIRECTION INPUT ;
    USE SIGNAL ;
    PORT
      LAYER M5 ;
        RECT  37.008 107.916 37.032 108 ;
    END
  END wd_in[8]
  PIN wd_in[9]
    DIRECTION INPUT ;
    USE SIGNAL ;
    PORT
      LAYER M5 ;
        RECT  37.152 107.916 37.176 108 ;
    END
  END wd_in[9]
  PIN VSS
    DIRECTION INOUT ;
    USE GROUND ;
    PORT
      LAYER M5 ;
        RECT  105 2.137 105.12 105.863 ;
        RECT  99.6 2.137 99.72 105.863 ;
        RECT  94.2 2.137 94.32 105.863 ;
        RECT  88.8 2.137 88.92 105.863 ;
        RECT  83.4 2.137 83.52 105.863 ;
        RECT  78 2.137 78.12 105.863 ;
        RECT  72.6 2.137 72.72 105.863 ;
        RECT  67.2 2.137 67.32 105.863 ;
        RECT  61.8 2.137 61.92 105.863 ;
        RECT  56.4 2.137 56.52 105.863 ;
        RECT  51 2.137 51.12 105.863 ;
        RECT  45.6 2.137 45.72 105.863 ;
        RECT  40.2 2.137 40.32 105.863 ;
        RECT  34.8 2.137 34.92 105.863 ;
        RECT  29.4 2.137 29.52 105.863 ;
        RECT  24 2.137 24.12 105.863 ;
        RECT  18.6 2.137 18.72 105.863 ;
        RECT  13.2 2.137 13.32 105.863 ;
        RECT  7.8 2.137 7.92 105.863 ;
        RECT  2.4 2.137 2.52 105.863 ;
    END
  END VSS
  PIN VDD
    DIRECTION INOUT ;
    USE POWER ;
    PORT
      LAYER M5 ;
        RECT  105.192 2.151 105.312 105.849 ;
        RECT  99.792 2.151 99.912 105.849 ;
        RECT  94.392 2.151 94.512 105.849 ;
        RECT  88.992 2.151 89.112 105.849 ;
        RECT  83.592 2.151 83.712 105.849 ;
        RECT  78.192 2.151 78.312 105.849 ;
        RECT  72.792 2.151 72.912 105.849 ;
        RECT  67.392 2.151 67.512 105.849 ;
        RECT  61.992 2.151 62.112 105.849 ;
        RECT  56.592 2.151 56.712 105.849 ;
        RECT  51.192 2.151 51.312 105.849 ;
        RECT  45.792 2.151 45.912 105.849 ;
        RECT  40.392 2.151 40.512 105.849 ;
        RECT  34.992 2.151 35.112 105.849 ;
        RECT  29.592 2.151 29.712 105.849 ;
        RECT  24.192 2.151 24.312 105.849 ;
        RECT  18.792 2.151 18.912 105.849 ;
        RECT  13.392 2.151 13.512 105.849 ;
        RECT  7.992 2.151 8.112 105.849 ;
        RECT  2.592 2.151 2.712 105.849 ;
    END
  END VDD
  # OT_OBS_CLOSED layer=M5 d_um=1.536 added=15
  OBS
    LAYER RVTN ;
     RECT  2.16 2.16 105.84 2.295 ;
     RECT  2.16 2.565 105.84 2.835 ;
     RECT  2.16 3.105 105.84 3.375 ;
     RECT  2.16 3.645 105.84 3.915 ;
     RECT  2.16 4.185 105.84 4.455 ;
     RECT  2.16 4.725 105.84 4.995 ;
     RECT  2.16 5.265 105.84 5.535 ;
     RECT  2.16 5.805 105.84 6.075 ;
     RECT  2.16 6.345 105.84 6.615 ;
     RECT  2.16 6.885 105.84 7.155 ;
     RECT  2.16 7.425 105.84 7.695 ;
     RECT  2.16 7.965 105.84 8.235 ;
     RECT  2.16 8.505 105.84 8.775 ;
     RECT  2.16 9.045 105.84 9.315 ;
     RECT  2.16 9.585 105.84 9.855 ;
     RECT  2.16 10.125 105.84 10.395 ;
     RECT  2.16 10.665 105.84 10.935 ;
     RECT  2.16 11.205 105.84 11.475 ;
     RECT  2.16 11.745 105.84 12.015 ;
     RECT  2.16 12.285 105.84 12.555 ;
     RECT  2.16 12.825 105.84 13.095 ;
     RECT  2.16 13.365 105.84 13.635 ;
     RECT  2.16 13.905 105.84 14.175 ;
     RECT  2.16 14.445 105.84 14.715 ;
     RECT  2.16 14.985 105.84 15.255 ;
     RECT  2.16 15.525 105.84 15.795 ;
     RECT  2.16 16.065 105.84 16.335 ;
     RECT  2.16 16.605 105.84 16.875 ;
     RECT  2.16 17.145 105.84 17.415 ;
     RECT  2.16 17.685 105.84 17.955 ;
     RECT  2.16 18.225 105.84 18.495 ;
     RECT  2.16 18.765 105.84 19.035 ;
     RECT  2.16 19.305 105.84 19.575 ;
     RECT  2.16 19.845 105.84 20.115 ;
     RECT  2.16 20.385 105.84 20.655 ;
     RECT  2.16 20.925 105.84 21.195 ;
     RECT  2.16 21.465 105.84 21.735 ;
     RECT  2.16 22.005 105.84 22.275 ;
     RECT  2.16 22.545 105.84 22.815 ;
     RECT  2.16 23.085 105.84 23.355 ;
     RECT  2.16 23.625 105.84 23.895 ;
     RECT  2.16 24.165 105.84 24.435 ;
     RECT  2.16 24.705 105.84 24.975 ;
     RECT  2.16 25.245 105.84 25.515 ;
     RECT  2.16 25.785 105.84 26.055 ;
     RECT  2.16 26.325 105.84 26.595 ;
     RECT  2.16 26.865 105.84 27.135 ;
     RECT  2.16 27.405 105.84 27.675 ;
     RECT  2.16 27.945 105.84 28.215 ;
     RECT  2.16 28.485 105.84 28.755 ;
     RECT  2.16 29.025 105.84 29.295 ;
     RECT  2.16 29.565 105.84 29.835 ;
     RECT  2.16 30.105 105.84 30.375 ;
     RECT  2.16 30.645 105.84 30.915 ;
     RECT  2.16 31.185 105.84 31.455 ;
     RECT  2.16 31.725 105.84 31.995 ;
     RECT  2.16 32.265 105.84 32.535 ;
     RECT  2.16 32.805 105.84 33.075 ;
     RECT  2.16 33.345 105.84 33.615 ;
     RECT  2.16 33.885 105.84 34.155 ;
     RECT  2.16 34.425 105.84 34.695 ;
     RECT  2.16 34.965 105.84 35.235 ;
     RECT  2.16 35.505 105.84 35.775 ;
     RECT  2.16 36.045 105.84 36.315 ;
     RECT  2.16 36.585 105.84 36.855 ;
     RECT  2.16 37.125 105.84 37.395 ;
     RECT  2.16 37.665 105.84 37.935 ;
     RECT  2.16 38.205 105.84 38.475 ;
     RECT  2.16 38.745 105.84 39.015 ;
     RECT  2.16 39.285 105.84 39.555 ;
     RECT  2.16 39.825 105.84 40.095 ;
     RECT  2.16 40.365 105.84 40.635 ;
     RECT  2.16 40.905 105.84 41.04 ;
     RECT  2.16 41.04 41.148 41.175 ;
     RECT  78.948 41.04 105.84 41.175 ;
     RECT  2.16 41.445 41.148 41.715 ;
     RECT  78.948 41.445 105.84 41.715 ;
     RECT  2.16 41.985 41.148 42.255 ;
     RECT  78.948 41.985 105.84 42.255 ;
     RECT  2.16 42.525 41.148 42.795 ;
     RECT  78.948 42.525 105.84 42.795 ;
     RECT  2.16 43.065 41.148 43.335 ;
     RECT  78.948 43.065 105.84 43.335 ;
     RECT  2.16 43.605 41.148 43.875 ;
     RECT  78.948 43.605 105.84 43.875 ;
     RECT  2.16 44.145 41.148 44.415 ;
     RECT  78.948 44.145 105.84 44.415 ;
     RECT  2.16 44.685 41.148 44.955 ;
     RECT  78.948 44.685 105.84 44.955 ;
     RECT  2.16 45.225 41.148 45.495 ;
     RECT  78.948 45.225 105.84 45.495 ;
     RECT  2.16 45.765 41.148 46.035 ;
     RECT  78.948 45.765 105.84 46.035 ;
     RECT  2.16 46.305 41.148 46.575 ;
     RECT  78.948 46.305 105.84 46.575 ;
     RECT  2.16 46.845 41.148 47.115 ;
     RECT  78.948 46.845 105.84 47.115 ;
     RECT  2.16 47.385 41.148 47.655 ;
     RECT  78.948 47.385 105.84 47.655 ;
     RECT  2.16 47.925 41.148 48.195 ;
     RECT  78.948 47.925 105.84 48.195 ;
     RECT  2.16 48.465 41.148 48.735 ;
     RECT  78.948 48.465 105.84 48.735 ;
     RECT  2.16 49.005 41.148 49.275 ;
     RECT  78.948 49.005 105.84 49.275 ;
     RECT  2.16 49.545 41.148 49.815 ;
     RECT  78.948 49.545 105.84 49.815 ;
     RECT  2.16 50.085 41.148 50.355 ;
     RECT  78.948 50.085 105.84 50.355 ;
     RECT  2.16 50.625 41.148 50.895 ;
     RECT  78.948 50.625 105.84 50.895 ;
     RECT  2.16 51.165 41.148 51.435 ;
     RECT  78.948 51.165 105.84 51.435 ;
     RECT  2.16 51.705 41.148 51.975 ;
     RECT  78.948 51.705 105.84 51.975 ;
     RECT  2.16 52.245 41.148 52.515 ;
     RECT  78.948 52.245 105.84 52.515 ;
     RECT  2.16 52.785 41.148 53.055 ;
     RECT  78.948 52.785 105.84 53.055 ;
     RECT  2.16 53.325 41.148 53.595 ;
     RECT  78.948 53.325 105.84 53.595 ;
     RECT  2.16 53.865 41.148 54.135 ;
     RECT  78.948 53.865 105.84 54.135 ;
     RECT  2.16 54.405 41.148 54.675 ;
     RECT  78.948 54.405 105.84 54.675 ;
     RECT  2.16 54.945 41.148 55.215 ;
     RECT  78.948 54.945 105.84 55.215 ;
     RECT  2.16 55.485 41.148 55.755 ;
     RECT  78.948 55.485 105.84 55.755 ;
     RECT  2.16 56.025 41.148 56.295 ;
     RECT  78.948 56.025 105.84 56.295 ;
     RECT  2.16 56.565 41.148 56.835 ;
     RECT  78.948 56.565 105.84 56.835 ;
     RECT  2.16 57.105 41.148 57.375 ;
     RECT  78.948 57.105 105.84 57.375 ;
     RECT  2.16 57.645 41.148 57.915 ;
     RECT  78.948 57.645 105.84 57.915 ;
     RECT  2.16 58.185 41.148 58.455 ;
     RECT  78.948 58.185 105.84 58.455 ;
     RECT  2.16 58.725 41.148 58.995 ;
     RECT  78.948 58.725 105.84 58.995 ;
     RECT  2.16 59.265 41.148 59.535 ;
     RECT  78.948 59.265 105.84 59.535 ;
     RECT  2.16 59.805 41.148 60.075 ;
     RECT  78.948 59.805 105.84 60.075 ;
     RECT  2.16 60.345 41.148 60.615 ;
     RECT  78.948 60.345 105.84 60.615 ;
     RECT  2.16 60.885 41.148 61.155 ;
     RECT  78.948 60.885 105.84 61.155 ;
     RECT  2.16 61.425 41.148 61.695 ;
     RECT  78.948 61.425 105.84 61.695 ;
     RECT  2.16 61.965 41.148 62.235 ;
     RECT  78.948 61.965 105.84 62.235 ;
     RECT  2.16 62.505 41.148 62.775 ;
     RECT  78.948 62.505 105.84 62.775 ;
     RECT  2.16 63.045 41.148 63.315 ;
     RECT  78.948 63.045 105.84 63.315 ;
     RECT  2.16 63.585 41.148 63.855 ;
     RECT  78.948 63.585 105.84 63.855 ;
     RECT  2.16 64.125 41.148 64.395 ;
     RECT  78.948 64.125 105.84 64.395 ;
     RECT  2.16 64.665 41.148 64.935 ;
     RECT  78.948 64.665 105.84 64.935 ;
     RECT  2.16 65.205 41.148 65.475 ;
     RECT  78.948 65.205 105.84 65.475 ;
     RECT  2.16 65.745 41.148 66.015 ;
     RECT  78.948 65.745 105.84 66.015 ;
     RECT  2.16 66.285 41.148 66.555 ;
     RECT  78.948 66.285 105.84 66.555 ;
     RECT  2.16 66.825 41.148 67.095 ;
     RECT  78.948 66.825 105.84 67.095 ;
     RECT  2.16 67.365 41.148 67.635 ;
     RECT  78.948 67.365 105.84 67.635 ;
     RECT  2.16 67.905 41.148 68.175 ;
     RECT  78.948 67.905 105.84 68.175 ;
     RECT  2.16 68.445 41.148 68.715 ;
     RECT  78.948 68.445 105.84 68.715 ;
     RECT  2.16 68.985 41.148 69.255 ;
     RECT  78.948 68.985 105.84 69.255 ;
     RECT  2.16 69.525 41.148 69.795 ;
     RECT  78.948 69.525 105.84 69.795 ;
     RECT  2.16 70.065 41.148 70.335 ;
     RECT  78.948 70.065 105.84 70.335 ;
     RECT  2.16 70.605 41.148 70.875 ;
     RECT  78.948 70.605 105.84 70.875 ;
     RECT  2.16 71.145 41.148 71.415 ;
     RECT  78.948 71.145 105.84 71.415 ;
     RECT  2.16 71.685 41.148 71.955 ;
     RECT  78.948 71.685 105.84 71.955 ;
     RECT  2.16 72.225 41.148 72.495 ;
     RECT  78.948 72.225 105.84 72.495 ;
     RECT  2.16 72.765 41.148 72.9 ;
     RECT  78.948 72.765 105.84 72.9 ;
     RECT  2.16 72.9 105.84 73.035 ;
     RECT  2.16 73.305 105.84 73.575 ;
     RECT  2.16 73.845 105.84 74.115 ;
     RECT  2.16 74.385 105.84 74.655 ;
     RECT  2.16 74.925 105.84 75.195 ;
     RECT  2.16 75.465 105.84 75.735 ;
     RECT  2.16 76.005 105.84 76.275 ;
     RECT  2.16 76.545 105.84 76.815 ;
     RECT  2.16 77.085 105.84 77.355 ;
     RECT  2.16 77.625 105.84 77.895 ;
     RECT  2.16 78.165 105.84 78.435 ;
     RECT  2.16 78.705 105.84 78.975 ;
     RECT  2.16 79.245 105.84 79.515 ;
     RECT  2.16 79.785 105.84 80.055 ;
     RECT  2.16 80.325 105.84 80.595 ;
     RECT  2.16 80.865 105.84 81.135 ;
     RECT  2.16 81.405 105.84 81.675 ;
     RECT  2.16 81.945 105.84 82.215 ;
     RECT  2.16 82.485 105.84 82.755 ;
     RECT  2.16 83.025 105.84 83.295 ;
     RECT  2.16 83.565 105.84 83.835 ;
     RECT  2.16 84.105 105.84 84.375 ;
     RECT  2.16 84.645 105.84 84.915 ;
     RECT  2.16 85.185 105.84 85.455 ;
     RECT  2.16 85.725 105.84 85.995 ;
     RECT  2.16 86.265 105.84 86.535 ;
     RECT  2.16 86.805 105.84 87.075 ;
     RECT  2.16 87.345 105.84 87.615 ;
     RECT  2.16 87.885 105.84 88.155 ;
     RECT  2.16 88.425 105.84 88.695 ;
     RECT  2.16 88.965 105.84 89.235 ;
     RECT  2.16 89.505 105.84 89.775 ;
     RECT  2.16 90.045 105.84 90.315 ;
     RECT  2.16 90.585 105.84 90.855 ;
     RECT  2.16 91.125 105.84 91.395 ;
     RECT  2.16 91.665 105.84 91.935 ;
     RECT  2.16 92.205 105.84 92.475 ;
     RECT  2.16 92.745 105.84 93.015 ;
     RECT  2.16 93.285 105.84 93.555 ;
     RECT  2.16 93.825 105.84 94.095 ;
     RECT  2.16 94.365 105.84 94.635 ;
     RECT  2.16 94.905 105.84 95.175 ;
     RECT  2.16 95.445 105.84 95.715 ;
     RECT  2.16 95.985 105.84 96.255 ;
     RECT  2.16 96.525 105.84 96.795 ;
     RECT  2.16 97.065 105.84 97.335 ;
     RECT  2.16 97.605 105.84 97.875 ;
     RECT  2.16 98.145 105.84 98.415 ;
     RECT  2.16 98.685 105.84 98.955 ;
     RECT  2.16 99.225 105.84 99.495 ;
     RECT  2.16 99.765 105.84 100.035 ;
     RECT  2.16 100.305 105.84 100.575 ;
     RECT  2.16 100.845 105.84 101.115 ;
     RECT  2.16 101.385 105.84 101.655 ;
     RECT  2.16 101.925 105.84 102.195 ;
     RECT  2.16 102.465 105.84 102.735 ;
     RECT  2.16 103.005 105.84 103.275 ;
     RECT  2.16 103.545 105.84 103.815 ;
     RECT  2.16 104.085 105.84 104.355 ;
     RECT  2.16 104.625 105.84 104.895 ;
     RECT  2.16 105.165 105.84 105.435 ;
     RECT  2.16 105.705 105.84 105.84 ;
    LAYER RVTP ;
     RECT  2.16 2.295 105.84 2.565 ;
     RECT  2.16 2.835 105.84 3.105 ;
     RECT  2.16 3.375 105.84 3.645 ;
     RECT  2.16 3.915 105.84 4.185 ;
     RECT  2.16 4.455 105.84 4.725 ;
     RECT  2.16 4.995 105.84 5.265 ;
     RECT  2.16 5.535 105.84 5.805 ;
     RECT  2.16 6.075 105.84 6.345 ;
     RECT  2.16 6.615 105.84 6.885 ;
     RECT  2.16 7.155 105.84 7.425 ;
     RECT  2.16 7.695 105.84 7.965 ;
     RECT  2.16 8.235 105.84 8.505 ;
     RECT  2.16 8.775 105.84 9.045 ;
     RECT  2.16 9.315 105.84 9.585 ;
     RECT  2.16 9.855 105.84 10.125 ;
     RECT  2.16 10.395 105.84 10.665 ;
     RECT  2.16 10.935 105.84 11.205 ;
     RECT  2.16 11.475 105.84 11.745 ;
     RECT  2.16 12.015 105.84 12.285 ;
     RECT  2.16 12.555 105.84 12.825 ;
     RECT  2.16 13.095 105.84 13.365 ;
     RECT  2.16 13.635 105.84 13.905 ;
     RECT  2.16 14.175 105.84 14.445 ;
     RECT  2.16 14.715 105.84 14.985 ;
     RECT  2.16 15.255 105.84 15.525 ;
     RECT  2.16 15.795 105.84 16.065 ;
     RECT  2.16 16.335 105.84 16.605 ;
     RECT  2.16 16.875 105.84 17.145 ;
     RECT  2.16 17.415 105.84 17.685 ;
     RECT  2.16 17.955 105.84 18.225 ;
     RECT  2.16 18.495 105.84 18.765 ;
     RECT  2.16 19.035 105.84 19.305 ;
     RECT  2.16 19.575 105.84 19.845 ;
     RECT  2.16 20.115 105.84 20.385 ;
     RECT  2.16 20.655 105.84 20.925 ;
     RECT  2.16 21.195 105.84 21.465 ;
     RECT  2.16 21.735 105.84 22.005 ;
     RECT  2.16 22.275 105.84 22.545 ;
     RECT  2.16 22.815 105.84 23.085 ;
     RECT  2.16 23.355 105.84 23.625 ;
     RECT  2.16 23.895 105.84 24.165 ;
     RECT  2.16 24.435 105.84 24.705 ;
     RECT  2.16 24.975 105.84 25.245 ;
     RECT  2.16 25.515 105.84 25.785 ;
     RECT  2.16 26.055 105.84 26.325 ;
     RECT  2.16 26.595 105.84 26.865 ;
     RECT  2.16 27.135 105.84 27.405 ;
     RECT  2.16 27.675 105.84 27.945 ;
     RECT  2.16 28.215 105.84 28.485 ;
     RECT  2.16 28.755 105.84 29.025 ;
     RECT  2.16 29.295 105.84 29.565 ;
     RECT  2.16 29.835 105.84 30.105 ;
     RECT  2.16 30.375 105.84 30.645 ;
     RECT  2.16 30.915 105.84 31.185 ;
     RECT  2.16 31.455 105.84 31.725 ;
     RECT  2.16 31.995 105.84 32.265 ;
     RECT  2.16 32.535 105.84 32.805 ;
     RECT  2.16 33.075 105.84 33.345 ;
     RECT  2.16 33.615 105.84 33.885 ;
     RECT  2.16 34.155 105.84 34.425 ;
     RECT  2.16 34.695 105.84 34.965 ;
     RECT  2.16 35.235 105.84 35.505 ;
     RECT  2.16 35.775 105.84 36.045 ;
     RECT  2.16 36.315 105.84 36.585 ;
     RECT  2.16 36.855 105.84 37.125 ;
     RECT  2.16 37.395 105.84 37.665 ;
     RECT  2.16 37.935 105.84 38.205 ;
     RECT  2.16 38.475 105.84 38.745 ;
     RECT  2.16 39.015 105.84 39.285 ;
     RECT  2.16 39.555 105.84 39.825 ;
     RECT  2.16 40.095 105.84 40.365 ;
     RECT  2.16 40.635 105.84 40.905 ;
     RECT  2.16 41.175 41.148 41.445 ;
     RECT  78.948 41.175 105.84 41.445 ;
     RECT  2.16 41.715 41.148 41.985 ;
     RECT  78.948 41.715 105.84 41.985 ;
     RECT  2.16 42.255 41.148 42.525 ;
     RECT  78.948 42.255 105.84 42.525 ;
     RECT  2.16 42.795 41.148 43.065 ;
     RECT  78.948 42.795 105.84 43.065 ;
     RECT  2.16 43.335 41.148 43.605 ;
     RECT  78.948 43.335 105.84 43.605 ;
     RECT  2.16 43.875 41.148 44.145 ;
     RECT  78.948 43.875 105.84 44.145 ;
     RECT  2.16 44.415 41.148 44.685 ;
     RECT  78.948 44.415 105.84 44.685 ;
     RECT  2.16 44.955 41.148 45.225 ;
     RECT  78.948 44.955 105.84 45.225 ;
     RECT  2.16 45.495 41.148 45.765 ;
     RECT  78.948 45.495 105.84 45.765 ;
     RECT  2.16 46.035 41.148 46.305 ;
     RECT  78.948 46.035 105.84 46.305 ;
     RECT  2.16 46.575 41.148 46.845 ;
     RECT  78.948 46.575 105.84 46.845 ;
     RECT  2.16 47.115 41.148 47.385 ;
     RECT  78.948 47.115 105.84 47.385 ;
     RECT  2.16 47.655 41.148 47.925 ;
     RECT  78.948 47.655 105.84 47.925 ;
     RECT  2.16 48.195 41.148 48.465 ;
     RECT  78.948 48.195 105.84 48.465 ;
     RECT  2.16 48.735 41.148 49.005 ;
     RECT  78.948 48.735 105.84 49.005 ;
     RECT  2.16 49.275 41.148 49.545 ;
     RECT  78.948 49.275 105.84 49.545 ;
     RECT  2.16 49.815 41.148 50.085 ;
     RECT  78.948 49.815 105.84 50.085 ;
     RECT  2.16 50.355 41.148 50.625 ;
     RECT  78.948 50.355 105.84 50.625 ;
     RECT  2.16 50.895 41.148 51.165 ;
     RECT  78.948 50.895 105.84 51.165 ;
     RECT  2.16 51.435 41.148 51.705 ;
     RECT  78.948 51.435 105.84 51.705 ;
     RECT  2.16 51.975 41.148 52.245 ;
     RECT  78.948 51.975 105.84 52.245 ;
     RECT  2.16 52.515 41.148 52.785 ;
     RECT  78.948 52.515 105.84 52.785 ;
     RECT  2.16 53.055 41.148 53.325 ;
     RECT  78.948 53.055 105.84 53.325 ;
     RECT  2.16 53.595 41.148 53.865 ;
     RECT  78.948 53.595 105.84 53.865 ;
     RECT  2.16 54.135 41.148 54.405 ;
     RECT  78.948 54.135 105.84 54.405 ;
     RECT  2.16 54.675 41.148 54.945 ;
     RECT  78.948 54.675 105.84 54.945 ;
     RECT  2.16 55.215 41.148 55.485 ;
     RECT  78.948 55.215 105.84 55.485 ;
     RECT  2.16 55.755 41.148 56.025 ;
     RECT  78.948 55.755 105.84 56.025 ;
     RECT  2.16 56.295 41.148 56.565 ;
     RECT  78.948 56.295 105.84 56.565 ;
     RECT  2.16 56.835 41.148 57.105 ;
     RECT  78.948 56.835 105.84 57.105 ;
     RECT  2.16 57.375 41.148 57.645 ;
     RECT  78.948 57.375 105.84 57.645 ;
     RECT  2.16 57.915 41.148 58.185 ;
     RECT  78.948 57.915 105.84 58.185 ;
     RECT  2.16 58.455 41.148 58.725 ;
     RECT  78.948 58.455 105.84 58.725 ;
     RECT  2.16 58.995 41.148 59.265 ;
     RECT  78.948 58.995 105.84 59.265 ;
     RECT  2.16 59.535 41.148 59.805 ;
     RECT  78.948 59.535 105.84 59.805 ;
     RECT  2.16 60.075 41.148 60.345 ;
     RECT  78.948 60.075 105.84 60.345 ;
     RECT  2.16 60.615 41.148 60.885 ;
     RECT  78.948 60.615 105.84 60.885 ;
     RECT  2.16 61.155 41.148 61.425 ;
     RECT  78.948 61.155 105.84 61.425 ;
     RECT  2.16 61.695 41.148 61.965 ;
     RECT  78.948 61.695 105.84 61.965 ;
     RECT  2.16 62.235 41.148 62.505 ;
     RECT  78.948 62.235 105.84 62.505 ;
     RECT  2.16 62.775 41.148 63.045 ;
     RECT  78.948 62.775 105.84 63.045 ;
     RECT  2.16 63.315 41.148 63.585 ;
     RECT  78.948 63.315 105.84 63.585 ;
     RECT  2.16 63.855 41.148 64.125 ;
     RECT  78.948 63.855 105.84 64.125 ;
     RECT  2.16 64.395 41.148 64.665 ;
     RECT  78.948 64.395 105.84 64.665 ;
     RECT  2.16 64.935 41.148 65.205 ;
     RECT  78.948 64.935 105.84 65.205 ;
     RECT  2.16 65.475 41.148 65.745 ;
     RECT  78.948 65.475 105.84 65.745 ;
     RECT  2.16 66.015 41.148 66.285 ;
     RECT  78.948 66.015 105.84 66.285 ;
     RECT  2.16 66.555 41.148 66.825 ;
     RECT  78.948 66.555 105.84 66.825 ;
     RECT  2.16 67.095 41.148 67.365 ;
     RECT  78.948 67.095 105.84 67.365 ;
     RECT  2.16 67.635 41.148 67.905 ;
     RECT  78.948 67.635 105.84 67.905 ;
     RECT  2.16 68.175 41.148 68.445 ;
     RECT  78.948 68.175 105.84 68.445 ;
     RECT  2.16 68.715 41.148 68.985 ;
     RECT  78.948 68.715 105.84 68.985 ;
     RECT  2.16 69.255 41.148 69.525 ;
     RECT  78.948 69.255 105.84 69.525 ;
     RECT  2.16 69.795 41.148 70.065 ;
     RECT  78.948 69.795 105.84 70.065 ;
     RECT  2.16 70.335 41.148 70.605 ;
     RECT  78.948 70.335 105.84 70.605 ;
     RECT  2.16 70.875 41.148 71.145 ;
     RECT  78.948 70.875 105.84 71.145 ;
     RECT  2.16 71.415 41.148 71.685 ;
     RECT  78.948 71.415 105.84 71.685 ;
     RECT  2.16 71.955 41.148 72.225 ;
     RECT  78.948 71.955 105.84 72.225 ;
     RECT  2.16 72.495 41.148 72.765 ;
     RECT  78.948 72.495 105.84 72.765 ;
     RECT  2.16 73.035 105.84 73.305 ;
     RECT  2.16 73.575 105.84 73.845 ;
     RECT  2.16 74.115 105.84 74.385 ;
     RECT  2.16 74.655 105.84 74.925 ;
     RECT  2.16 75.195 105.84 75.465 ;
     RECT  2.16 75.735 105.84 76.005 ;
     RECT  2.16 76.275 105.84 76.545 ;
     RECT  2.16 76.815 105.84 77.085 ;
     RECT  2.16 77.355 105.84 77.625 ;
     RECT  2.16 77.895 105.84 78.165 ;
     RECT  2.16 78.435 105.84 78.705 ;
     RECT  2.16 78.975 105.84 79.245 ;
     RECT  2.16 79.515 105.84 79.785 ;
     RECT  2.16 80.055 105.84 80.325 ;
     RECT  2.16 80.595 105.84 80.865 ;
     RECT  2.16 81.135 105.84 81.405 ;
     RECT  2.16 81.675 105.84 81.945 ;
     RECT  2.16 82.215 105.84 82.485 ;
     RECT  2.16 82.755 105.84 83.025 ;
     RECT  2.16 83.295 105.84 83.565 ;
     RECT  2.16 83.835 105.84 84.105 ;
     RECT  2.16 84.375 105.84 84.645 ;
     RECT  2.16 84.915 105.84 85.185 ;
     RECT  2.16 85.455 105.84 85.725 ;
     RECT  2.16 85.995 105.84 86.265 ;
     RECT  2.16 86.535 105.84 86.805 ;
     RECT  2.16 87.075 105.84 87.345 ;
     RECT  2.16 87.615 105.84 87.885 ;
     RECT  2.16 88.155 105.84 88.425 ;
     RECT  2.16 88.695 105.84 88.965 ;
     RECT  2.16 89.235 105.84 89.505 ;
     RECT  2.16 89.775 105.84 90.045 ;
     RECT  2.16 90.315 105.84 90.585 ;
     RECT  2.16 90.855 105.84 91.125 ;
     RECT  2.16 91.395 105.84 91.665 ;
     RECT  2.16 91.935 105.84 92.205 ;
     RECT  2.16 92.475 105.84 92.745 ;
     RECT  2.16 93.015 105.84 93.285 ;
     RECT  2.16 93.555 105.84 93.825 ;
     RECT  2.16 94.095 105.84 94.365 ;
     RECT  2.16 94.635 105.84 94.905 ;
     RECT  2.16 95.175 105.84 95.445 ;
     RECT  2.16 95.715 105.84 95.985 ;
     RECT  2.16 96.255 105.84 96.525 ;
     RECT  2.16 96.795 105.84 97.065 ;
     RECT  2.16 97.335 105.84 97.605 ;
     RECT  2.16 97.875 105.84 98.145 ;
     RECT  2.16 98.415 105.84 98.685 ;
     RECT  2.16 98.955 105.84 99.225 ;
     RECT  2.16 99.495 105.84 99.765 ;
     RECT  2.16 100.035 105.84 100.305 ;
     RECT  2.16 100.575 105.84 100.845 ;
     RECT  2.16 101.115 105.84 101.385 ;
     RECT  2.16 101.655 105.84 101.925 ;
     RECT  2.16 102.195 105.84 102.465 ;
     RECT  2.16 102.735 105.84 103.005 ;
     RECT  2.16 103.275 105.84 103.545 ;
     RECT  2.16 103.815 105.84 104.085 ;
     RECT  2.16 104.355 105.84 104.625 ;
     RECT  2.16 104.895 105.84 105.165 ;
     RECT  2.16 105.435 105.84 105.705 ;
    LAYER M1 ;
     RECT  2.16 2.151 105.84 41.049 ;
     RECT  43.2 43.2 76.92 70.776 ;
     RECT  2.16 41.049 41.148 72.891 ;
     RECT  78.948 41.049 105.84 72.891 ;
     RECT  2.16 72.891 105.84 105.849 ;
    LAYER M2 ;
     RECT  0.103 47.592 0.535 47.61 ;
     RECT  0.535 47.16 1.723 47.682 ;
     RECT  1.723 47.16 2.16 47.88 ;
     RECT  0.103 48.672 2.16 48.69 ;
     RECT  0.103 49.482 2.16 49.5 ;
     RECT  2.16 2.151 41.148 105.849 ;
     RECT  41.148 44.46 41.171 47.646 ;
     RECT  41.171 45.576 41.243 47.646 ;
     RECT  41.243 45.666 41.315 47.646 ;
     RECT  41.315 45.666 41.387 45.684 ;
     RECT  41.171 44.46 41.531 44.784 ;
     RECT  41.315 46.701 41.531 47.646 ;
     RECT  41.148 51.516 41.531 54.936 ;
     RECT  41.531 46.701 41.567 47.304 ;
     RECT  41.531 51.516 41.567 54.864 ;
     RECT  41.531 44.46 41.603 44.478 ;
     RECT  41.567 47.196 41.603 47.304 ;
     RECT  41.567 51.516 41.639 54.324 ;
     RECT  41.148 2.151 42.043 42.084 ;
     RECT  41.148 42.876 42.043 43.254 ;
     RECT  41.148 49.824 42.215 50.454 ;
     RECT  42.043 2.151 42.323 43.254 ;
     RECT  42.943 44.388 43.015 44.406 ;
     RECT  42.323 2.151 43.2 43.164 ;
     RECT  43.015 44.388 43.2 44.676 ;
     RECT  42.215 49.824 43.2 49.914 ;
     RECT  41.639 51.876 43.2 54.324 ;
     RECT  43.2 2.151 76.92 70.776 ;
     RECT  76.92 49.896 78.007 50.994 ;
     RECT  76.92 51.948 78.007 51.966 ;
     RECT  78.007 49.896 78.043 52.236 ;
     RECT  76.92 46.206 78.079 46.224 ;
     RECT  78.079 46.206 78.691 46.8 ;
     RECT  76.92 48.51 78.763 48.996 ;
     RECT  78.043 49.896 78.763 52.344 ;
     RECT  78.763 48.51 78.835 52.344 ;
     RECT  76.92 2.151 78.948 43.704 ;
     RECT  78.691 46.206 78.948 46.872 ;
     RECT  78.835 47.826 78.948 52.344 ;
     RECT  41.148 72.891 78.948 105.849 ;
     RECT  78.948 2.151 105.84 105.849 ;
     RECT  105.84 43.236 106.619 52.272 ;
     RECT  106.619 43.686 107.159 52.272 ;
     RECT  107.159 43.686 107.195 44.442 ;
     RECT  107.159 45.27 107.195 45.288 ;
     RECT  107.159 47.124 107.195 50.148 ;
     RECT  107.159 51.138 107.195 51.264 ;
     RECT  107.159 52.254 107.195 52.272 ;
     RECT  107.195 47.286 107.231 48.294 ;
     RECT  107.159 46.044 107.879 46.332 ;
     RECT  107.195 44.226 107.915 44.244 ;
     RECT  107.879 46.044 107.915 46.062 ;
     RECT  107.231 48.276 107.915 48.294 ;
     RECT  107.195 49.446 107.915 50.148 ;
     RECT  107.195 51.246 107.915 51.264 ;
    LAYER M3 ;
     RECT  80.712 0.091 80.73 1.051 ;
     RECT  77.544 1.099 77.562 1.147 ;
     RECT  76.5 0.091 76.518 1.243 ;
     RECT  77.544 1.147 78.786 1.243 ;
     RECT  79.956 1.147 79.974 1.243 ;
     RECT  80.712 1.051 81.018 1.627 ;
     RECT  76.5 1.243 79.974 1.723 ;
     RECT  80.712 1.627 81.45 1.723 ;
     RECT  84.96 1.147 85.698 1.723 ;
     RECT  76.5 1.723 85.95 1.771 ;
     RECT  76.5 1.771 86.022 2.191 ;
     RECT  76.5 2.191 86.202 2.255 ;
     RECT  2.415 2.143 2.505 2.413 ;
     RECT  7.815 2.143 7.905 2.413 ;
     RECT  13.215 2.143 13.305 2.413 ;
     RECT  18.615 2.143 18.705 2.413 ;
     RECT  24.015 2.143 24.105 2.413 ;
     RECT  29.415 2.143 29.505 2.413 ;
     RECT  34.815 2.143 34.905 2.413 ;
     RECT  40.215 2.143 40.305 2.413 ;
     RECT  45.615 2.143 45.705 2.413 ;
     RECT  51.015 2.143 51.105 2.413 ;
     RECT  56.415 2.143 56.505 2.413 ;
     RECT  61.815 2.143 61.905 2.413 ;
     RECT  67.215 2.143 67.305 2.413 ;
     RECT  72.615 2.143 72.705 2.413 ;
     RECT  88.815 2.143 88.905 2.413 ;
     RECT  94.215 2.143 94.305 2.413 ;
     RECT  99.615 2.143 99.705 2.413 ;
     RECT  105.015 2.143 105.105 2.413 ;
     RECT  76.608 2.255 86.202 2.641 ;
     RECT  76.608 2.641 86.238 3.181 ;
     RECT  76.608 3.181 86.49 3.691 ;
     RECT  76.032 3.691 86.49 3.839 ;
     RECT  76.932 3.839 86.49 4.261 ;
     RECT  76.932 4.261 86.526 4.685 ;
     RECT  66.06 30.847 66.078 30.893 ;
     RECT  66.384 30.991 66.402 31.325 ;
     RECT  76.932 4.685 76.95 34.861 ;
     RECT  77.832 4.685 86.526 34.861 ;
     RECT  76.932 34.861 86.526 36.509 ;
     RECT  40.215 2.413 40.497 38.551 ;
     RECT  99.615 2.413 99.897 38.677 ;
     RECT  99.615 38.677 100.386 38.683 ;
     RECT  39.816 38.551 40.497 39.289 ;
     RECT  99.615 38.683 101.07 39.289 ;
     RECT  103.824 38.731 103.842 39.307 ;
     RECT  41.544 39.691 41.562 39.757 ;
     RECT  99.432 39.289 101.07 39.757 ;
     RECT  102.528 38.713 102.546 39.787 ;
     RECT  41.472 39.757 41.562 39.793 ;
     RECT  99.432 39.757 101.106 39.793 ;
     RECT  39.78 39.289 40.497 39.829 ;
     RECT  41.472 39.793 41.598 39.829 ;
     RECT  102.528 39.787 102.582 39.865 ;
     RECT  39.78 39.829 41.598 40.099 ;
     RECT  43.02 40.099 43.038 40.171 ;
     RECT  39.78 40.099 41.814 40.261 ;
     RECT  43.02 40.171 43.146 40.261 ;
     RECT  51.015 2.413 51.297 40.297 ;
     RECT  39.78 40.261 42.246 40.369 ;
     RECT  99.432 39.793 101.394 40.405 ;
     RECT  39.708 40.369 42.246 40.411 ;
     RECT  42.984 40.261 43.146 40.411 ;
     RECT  102.528 39.865 103.086 40.441 ;
     RECT  39.708 40.411 43.146 40.555 ;
     RECT  39.708 40.555 43.542 40.595 ;
     RECT  50.796 40.297 51.297 40.603 ;
     RECT  54.792 40.297 54.81 40.603 ;
     RECT  54.72 40.603 54.81 40.639 ;
     RECT  54.72 40.639 55.422 40.685 ;
     RECT  56.415 2.413 56.697 40.699 ;
     RECT  50.724 40.603 51.297 40.733 ;
     RECT  45.615 2.413 45.897 40.787 ;
     RECT  51.015 40.733 51.297 40.787 ;
     RECT  61.815 2.413 62.097 40.787 ;
     RECT  67.215 2.413 67.497 40.787 ;
     RECT  72.615 2.413 72.897 40.787 ;
     RECT  53.928 40.675 53.946 40.792 ;
     RECT  54.72 40.685 54.738 40.792 ;
     RECT  42.66 40.595 43.542 40.829 ;
     RECT  53.928 40.792 54.738 40.829 ;
     RECT  54.036 40.829 54.738 40.877 ;
     RECT  56.415 40.699 56.79 40.877 ;
     RECT  54.036 40.877 54.054 40.925 ;
     RECT  42.66 40.829 43.326 40.973 ;
     RECT  102.168 40.441 103.086 40.981 ;
     RECT  103.824 39.307 104.274 40.981 ;
     RECT  45.615 40.787 45.705 41.057 ;
     RECT  51.015 40.787 51.105 41.057 ;
     RECT  56.415 40.877 56.505 41.057 ;
     RECT  61.815 40.787 61.905 41.057 ;
     RECT  67.215 40.787 67.305 41.057 ;
     RECT  72.615 40.787 72.705 41.057 ;
     RECT  77.112 36.509 86.526 41.057 ;
     RECT  78.66 41.057 86.526 41.341 ;
     RECT  88.815 2.413 89.097 41.341 ;
     RECT  39.708 40.595 41.886 41.377 ;
     RECT  42.66 40.973 43.146 41.377 ;
     RECT  78.66 41.341 86.67 41.449 ;
     RECT  98.604 41.341 98.622 41.449 ;
     RECT  99.396 40.405 101.394 41.449 ;
     RECT  98.604 41.449 101.394 41.485 ;
     RECT  102.168 40.981 104.274 41.485 ;
     RECT  88.815 41.341 89.154 41.512 ;
     RECT  88.704 41.512 89.154 41.549 ;
     RECT  98.604 41.485 104.274 41.549 ;
     RECT  88.815 41.549 89.154 41.719 ;
     RECT  95.472 41.659 95.49 41.755 ;
     RECT  95.472 41.755 96.03 41.899 ;
     RECT  88.815 41.719 89.334 41.909 ;
     RECT  78.66 41.449 86.742 41.947 ;
     RECT  95.472 41.899 96.606 41.947 ;
     RECT  88.815 41.909 89.154 41.981 ;
     RECT  78.66 41.947 86.85 42.077 ;
     RECT  95.472 41.947 97.182 42.331 ;
     RECT  98.316 41.995 98.334 42.457 ;
     RECT  98.316 42.457 98.37 42.493 ;
     RECT  99.396 41.549 104.274 42.493 ;
     RECT  77.112 41.057 77.886 42.871 ;
     RECT  77.004 42.871 77.886 43.033 ;
     RECT  39.708 41.377 43.146 43.2 ;
     RECT  76.968 43.033 77.886 43.2 ;
     RECT  98.316 42.493 104.274 43.303 ;
     RECT  105.015 2.413 105.297 43.303 ;
     RECT  106.596 43.231 106.614 43.483 ;
     RECT  106.56 43.483 106.614 43.529 ;
     RECT  106.596 43.529 106.614 43.681 ;
     RECT  33.984 43.915 34.002 44.069 ;
     RECT  32.436 44.041 32.454 44.141 ;
     RECT  106.596 43.681 107.19 44.203 ;
     RECT  106.596 44.203 107.91 44.249 ;
     RECT  106.596 44.249 107.19 44.381 ;
     RECT  107.136 44.381 107.19 44.525 ;
     RECT  98.316 43.303 105.297 44.581 ;
     RECT  98.316 44.581 105.426 44.879 ;
     RECT  98.316 44.879 105.297 44.951 ;
     RECT  23.184 45.019 23.202 45.149 ;
     RECT  107.136 44.525 107.154 45.211 ;
     RECT  106.56 45.211 107.154 45.265 ;
     RECT  21.636 45.211 21.654 45.329 ;
     RECT  98.316 44.951 104.274 45.931 ;
     RECT  105.015 44.951 105.297 45.931 ;
     RECT  106.56 45.265 107.19 45.931 ;
     RECT  39.708 43.2 77.886 45.979 ;
     RECT  78.66 42.077 86.526 45.979 ;
     RECT  98.316 45.931 105.297 46.067 ;
     RECT  106.56 45.931 107.91 46.067 ;
     RECT  12.384 46.219 12.402 46.265 ;
     RECT  10.944 46.267 10.962 46.273 ;
     RECT  10.872 46.273 10.962 46.307 ;
     RECT  106.56 46.067 107.874 46.337 ;
     RECT  106.56 46.337 107.154 46.363 ;
     RECT  10.872 46.307 10.89 46.373 ;
     RECT  98.316 46.067 104.274 46.499 ;
     RECT  105.015 46.067 105.297 46.507 ;
     RECT  106.524 46.363 107.154 46.507 ;
     RECT  105.015 46.507 107.154 46.571 ;
     RECT  39.708 45.979 86.526 46.805 ;
     RECT  106.596 46.571 107.154 47.119 ;
     RECT  106.596 47.119 107.19 47.281 ;
     RECT  2.415 2.413 2.697 47.317 ;
     RECT  2.415 47.317 2.862 47.353 ;
     RECT  7.056 47.317 7.074 47.353 ;
     RECT  4.572 47.155 4.59 47.371 ;
     RECT  4.176 47.371 4.59 47.425 ;
     RECT  5.832 47.389 5.85 47.461 ;
     RECT  6.948 47.353 7.074 47.461 ;
     RECT  105.015 46.571 105.858 47.461 ;
     RECT  106.596 47.281 107.226 47.461 ;
     RECT  0.54 47.155 0.558 47.515 ;
     RECT  38.808 46.849 38.826 47.551 ;
     RECT  4.176 47.425 4.698 47.563 ;
     RECT  10.764 47.425 10.782 47.579 ;
     RECT  6.768 47.461 7.074 47.587 ;
     RECT  7.815 2.413 8.097 47.587 ;
     RECT  0.108 47.515 0.558 47.615 ;
     RECT  38.196 47.551 38.826 47.687 ;
     RECT  39.708 46.805 77.886 47.695 ;
     RECT  6.768 47.587 8.097 47.707 ;
     RECT  98.316 46.499 98.37 47.731 ;
     RECT  99.432 46.499 104.274 47.731 ;
     RECT  105.015 47.461 107.226 47.731 ;
     RECT  6.768 47.707 8.226 47.759 ;
     RECT  95.436 42.331 97.182 47.759 ;
     RECT  98.316 47.731 107.226 47.759 ;
     RECT  0.54 47.615 0.558 47.837 ;
     RECT  2.415 47.353 2.934 47.849 ;
     RECT  5.832 47.461 5.994 47.849 ;
     RECT  6.768 47.759 6.966 47.849 ;
     RECT  7.74 47.759 8.226 47.849 ;
     RECT  9.144 47.731 9.162 47.849 ;
     RECT  39.564 47.695 77.886 47.849 ;
     RECT  98.316 47.759 105.297 47.849 ;
     RECT  2.415 47.849 2.697 47.857 ;
     RECT  7.812 47.849 8.226 47.885 ;
     RECT  98.316 47.849 104.274 47.891 ;
     RECT  1.728 47.857 2.697 48.125 ;
     RECT  4.176 47.563 4.914 48.235 ;
     RECT  106.596 47.759 107.226 48.235 ;
     RECT  5.904 47.849 5.994 48.271 ;
     RECT  7.815 47.885 8.226 48.271 ;
     RECT  106.596 48.235 107.91 48.299 ;
     RECT  7.815 48.271 8.37 48.389 ;
     RECT  38.196 47.687 38.214 48.389 ;
     RECT  39.708 47.849 77.886 48.605 ;
     RECT  5.904 48.271 6.462 48.631 ;
     RECT  39.708 48.605 42.174 48.631 ;
     RECT  106.596 48.299 107.19 48.631 ;
     RECT  98.316 47.891 98.622 48.659 ;
     RECT  4.176 48.235 5.166 48.667 ;
     RECT  5.904 48.631 6.93 48.731 ;
     RECT  4.14 48.667 5.166 48.811 ;
     RECT  39.492 48.631 42.174 48.811 ;
     RECT  43.092 48.605 77.886 48.811 ;
     RECT  78.66 46.805 86.526 48.811 ;
     RECT  99.468 47.891 104.274 48.811 ;
     RECT  105.015 47.849 105.297 48.811 ;
     RECT  106.56 48.631 107.19 48.811 ;
     RECT  98.316 48.659 98.334 48.929 ;
     RECT  99.468 48.811 107.19 48.929 ;
     RECT  2.415 48.125 2.697 48.955 ;
     RECT  4.068 48.811 5.166 48.973 ;
     RECT  5.904 48.731 6.858 48.973 ;
     RECT  105.015 48.929 107.19 48.989 ;
     RECT  7.815 48.389 8.097 49.003 ;
     RECT  4.068 48.973 6.858 49.037 ;
     RECT  4.068 49.037 5.742 49.073 ;
     RECT  107.1 48.989 107.19 49.133 ;
     RECT  2.304 48.955 2.697 49.235 ;
     RECT  4.068 49.073 5.67 49.243 ;
     RECT  10.8 49.081 10.818 49.243 ;
     RECT  105.015 48.989 106.002 49.277 ;
     RECT  3.744 49.243 5.67 49.28 ;
     RECT  2.415 49.235 2.697 49.339 ;
     RECT  2.415 49.339 2.79 49.379 ;
     RECT  10.728 49.243 10.818 49.379 ;
     RECT  4.14 49.28 5.67 49.469 ;
     RECT  97.164 47.759 97.182 49.469 ;
     RECT  0.108 48.523 0.126 49.505 ;
     RECT  6.624 49.037 6.858 49.541 ;
     RECT  4.14 49.469 4.158 49.577 ;
     RECT  5.004 49.469 5.67 49.577 ;
     RECT  6.66 49.541 6.858 49.577 ;
     RECT  43.092 48.811 86.526 49.579 ;
     RECT  99.468 48.929 104.274 49.585 ;
     RECT  6.84 49.577 6.858 49.621 ;
     RECT  7.704 49.003 8.097 49.621 ;
     RECT  5.508 49.577 5.67 49.739 ;
     RECT  6.84 49.621 8.097 49.739 ;
     RECT  107.1 49.133 107.154 49.819 ;
     RECT  43.056 49.579 86.526 49.853 ;
     RECT  38.772 48.811 42.174 49.891 ;
     RECT  43.056 49.853 85.554 49.891 ;
     RECT  99.072 49.585 104.274 49.891 ;
     RECT  105.015 49.277 105.297 49.891 ;
     RECT  38.772 49.891 85.554 50.009 ;
     RECT  95.436 47.759 96.03 50.009 ;
     RECT  99.072 49.891 105.297 50.009 ;
     RECT  86.328 49.853 86.526 50.081 ;
     RECT  99.072 50.009 102.15 50.153 ;
     RECT  107.892 49.387 107.91 50.153 ;
     RECT  35.928 49.747 35.946 50.189 ;
     RECT  37.62 49.351 37.638 50.279 ;
     RECT  86.364 50.081 86.526 50.279 ;
     RECT  102.888 50.009 105.297 50.359 ;
     RECT  106.56 49.819 107.154 50.359 ;
     RECT  86.436 50.279 86.526 50.459 ;
     RECT  39.348 50.009 85.554 50.549 ;
     RECT  86.436 50.459 86.454 50.549 ;
     RECT  99.468 50.153 102.15 50.549 ;
     RECT  102.888 50.359 107.154 50.549 ;
     RECT  105.015 50.549 107.154 50.573 ;
     RECT  106.596 50.573 107.154 50.683 ;
     RECT  99.468 50.549 100.638 50.819 ;
     RECT  102.888 50.549 104.274 50.819 ;
     RECT  101.376 50.549 102.15 50.827 ;
     RECT  102.888 50.819 104.094 50.827 ;
     RECT  39.42 50.549 85.554 50.909 ;
     RECT  101.376 50.827 104.094 51.005 ;
     RECT  99.468 50.819 100.53 51.089 ;
     RECT  101.376 51.005 103.95 51.089 ;
     RECT  40.176 50.909 85.554 51.101 ;
     RECT  106.596 50.683 107.19 51.115 ;
     RECT  42.768 51.101 85.554 51.149 ;
     RECT  106.596 51.115 107.91 51.161 ;
     RECT  39.42 50.909 39.438 51.197 ;
     RECT  105.015 50.573 105.714 51.197 ;
     RECT  107.892 51.161 107.91 51.269 ;
     RECT  99.468 51.089 99.897 51.355 ;
     RECT  95.436 50.009 95.454 51.359 ;
     RECT  98.964 51.355 99.897 51.395 ;
     RECT  106.596 51.161 107.154 51.437 ;
     RECT  105.015 51.197 105.642 51.511 ;
     RECT  40.176 51.101 41.634 51.581 ;
     RECT  101.376 51.089 103.914 51.629 ;
     RECT  42.768 51.149 85.302 51.677 ;
     RECT  40.176 51.581 41.238 51.773 ;
     RECT  103.068 51.629 103.086 51.821 ;
     RECT  101.376 51.629 102.15 51.899 ;
     RECT  101.376 51.899 101.574 51.907 ;
     RECT  42.768 51.677 77.274 51.931 ;
     RECT  42.732 51.931 77.274 51.971 ;
     RECT  99.396 51.395 99.897 52.051 ;
     RECT  101.088 51.907 101.574 52.051 ;
     RECT  78.012 51.677 85.302 52.169 ;
     RECT  99.396 52.051 101.574 52.169 ;
     RECT  104.904 51.511 105.642 52.169 ;
     RECT  107.136 51.437 107.154 52.169 ;
     RECT  99.396 52.169 101.394 52.205 ;
     RECT  37.368 52.051 37.386 52.321 ;
     RECT  99.615 52.205 101.394 52.349 ;
     RECT  79.092 52.169 85.302 52.439 ;
     RECT  99.615 52.349 100.35 52.439 ;
     RECT  107.172 52.249 107.19 52.445 ;
     RECT  103.896 51.629 103.914 52.459 ;
     RECT  78.012 52.169 78.066 52.541 ;
     RECT  37.368 52.321 38.25 52.555 ;
     RECT  103.644 52.459 103.914 52.591 ;
     RECT  104.904 52.169 105.498 52.591 ;
     RECT  40.215 51.773 41.238 52.699 ;
     RECT  42.732 51.971 76.92 52.709 ;
     RECT  101.088 52.349 101.394 52.709 ;
     RECT  103.644 52.591 105.498 52.709 ;
     RECT  103.644 52.709 103.662 52.745 ;
     RECT  78.012 52.541 78.03 52.829 ;
     RECT  101.088 52.709 101.106 52.853 ;
     RECT  105.015 52.709 105.498 52.853 ;
     RECT  40.215 52.699 41.598 52.987 ;
     RECT  37.368 52.555 38.79 53.023 ;
     RECT  39.528 52.987 41.598 53.023 ;
     RECT  42.948 52.709 76.92 53.357 ;
     RECT  37.368 53.023 41.598 53.371 ;
     RECT  37.368 53.371 41.634 53.755 ;
     RECT  43.056 53.357 76.92 53.789 ;
     RECT  37.368 53.755 42.174 54.059 ;
     RECT  37.368 54.059 41.598 54.239 ;
     RECT  43.092 53.789 76.92 54.329 ;
     RECT  37.368 54.239 41.562 54.869 ;
     RECT  37.368 54.869 41.526 54.941 ;
     RECT  43.2 54.329 76.92 70.776 ;
     RECT  45.615 72.883 45.705 73.153 ;
     RECT  51.015 72.883 51.105 73.153 ;
     RECT  56.415 72.883 56.505 73.153 ;
     RECT  61.815 72.883 61.905 73.153 ;
     RECT  67.215 72.883 67.305 73.153 ;
     RECT  72.615 72.883 72.705 73.153 ;
     RECT  78.015 72.883 78.105 73.153 ;
     RECT  79.2 52.439 85.302 95.207 ;
     RECT  79.668 95.207 85.302 101.579 ;
     RECT  79.74 101.579 85.302 101.759 ;
     RECT  80.424 101.759 85.302 102.901 ;
     RECT  36.396 103.207 36.414 103.351 ;
     RECT  37.368 54.941 41.238 103.351 ;
     RECT  80.064 102.901 85.302 103.621 ;
     RECT  36.396 103.351 41.238 103.855 ;
     RECT  79.956 103.621 85.302 103.855 ;
     RECT  79.848 103.855 85.302 104.009 ;
     RECT  79.848 104.009 85.086 104.279 ;
     RECT  36.036 103.855 41.238 104.287 ;
     RECT  35.964 104.287 41.238 104.549 ;
     RECT  36.036 104.549 40.77 104.819 ;
     RECT  79.848 104.279 84.654 104.821 ;
     RECT  79.776 104.821 84.654 104.861 ;
     RECT  79.884 104.861 84.654 105.359 ;
     RECT  36.036 104.819 40.698 105.367 ;
     RECT  35.892 105.367 40.698 105.485 ;
     RECT  2.415 49.379 2.697 105.587 ;
     RECT  7.815 49.739 8.097 105.587 ;
     RECT  13.215 2.413 13.497 105.587 ;
     RECT  18.615 2.413 18.897 105.587 ;
     RECT  24.015 2.413 24.297 105.587 ;
     RECT  29.415 2.413 29.697 105.587 ;
     RECT  34.815 2.413 35.097 105.587 ;
     RECT  45.615 73.153 45.897 105.587 ;
     RECT  51.015 73.153 51.297 105.587 ;
     RECT  56.415 73.153 56.697 105.587 ;
     RECT  61.815 73.153 62.097 105.587 ;
     RECT  67.215 73.153 67.497 105.587 ;
     RECT  72.615 73.153 72.897 105.587 ;
     RECT  78.015 73.153 78.297 105.587 ;
     RECT  88.815 41.981 89.097 105.587 ;
     RECT  94.215 2.413 94.497 105.587 ;
     RECT  99.615 52.439 99.897 105.587 ;
     RECT  105.015 52.853 105.297 105.587 ;
     RECT  36.468 105.485 37.35 105.629 ;
     RECT  79.884 105.359 84.51 105.629 ;
     RECT  36.468 105.629 37.17 105.665 ;
     RECT  38.268 105.485 38.502 105.665 ;
     RECT  39.348 105.485 40.698 105.665 ;
     RECT  79.884 105.629 84.186 105.745 ;
     RECT  38.484 105.665 38.502 105.809 ;
     RECT  39.384 105.665 40.698 105.809 ;
     RECT  36.468 105.665 36.882 105.821 ;
     RECT  79.668 105.745 84.186 105.821 ;
     RECT  2.415 105.587 2.505 105.857 ;
     RECT  7.815 105.587 7.905 105.857 ;
     RECT  13.215 105.587 13.305 105.857 ;
     RECT  18.615 105.587 18.705 105.857 ;
     RECT  24.015 105.587 24.105 105.857 ;
     RECT  29.415 105.587 29.505 105.857 ;
     RECT  34.815 105.587 34.905 105.857 ;
     RECT  45.615 105.587 45.705 105.857 ;
     RECT  51.015 105.587 51.105 105.857 ;
     RECT  56.415 105.587 56.505 105.857 ;
     RECT  61.815 105.587 61.905 105.857 ;
     RECT  67.215 105.587 67.305 105.857 ;
     RECT  72.615 105.587 72.705 105.857 ;
     RECT  78.015 105.587 78.105 105.857 ;
     RECT  83.415 105.821 84.186 105.857 ;
     RECT  88.815 105.587 88.905 105.857 ;
     RECT  94.215 105.587 94.305 105.857 ;
     RECT  99.615 105.587 99.705 105.857 ;
     RECT  105.015 105.587 105.105 105.857 ;
     RECT  83.556 105.857 84.186 105.869 ;
     RECT  83.556 105.869 83.754 105.965 ;
     RECT  36.864 105.821 36.882 106.013 ;
     RECT  39.384 105.809 40.662 106.013 ;
     RECT  79.956 105.821 82.062 106.013 ;
     RECT  83.736 105.965 83.754 106.013 ;
     RECT  39.384 106.013 39.402 106.061 ;
     RECT  40.644 106.013 40.662 106.061 ;
     RECT  79.956 106.013 81.018 106.061 ;
     RECT  81 106.061 81.018 106.109 ;
     RECT  79.956 106.061 79.974 107.213 ;
     RECT  82.044 106.013 82.062 107.213 ;
    LAYER M4 ;
     RECT  0.084 47.088 2.408 47.112 ;
     RECT  0.06 47.112 2.408 47.232 ;
     RECT  0.084 47.232 2.408 47.256 ;
     RECT  0.06 47.256 2.408 47.376 ;
     RECT  0.084 47.376 2.408 47.4 ;
     RECT  0.06 47.4 2.408 47.52 ;
     RECT  0.084 47.52 2.408 47.544 ;
     RECT  0.06 47.544 2.408 47.664 ;
     RECT  0.084 47.664 2.408 47.688 ;
     RECT  0.06 47.688 2.408 47.808 ;
     RECT  0.084 47.808 2.408 47.832 ;
     RECT  0.06 47.832 2.408 47.952 ;
     RECT  0.084 47.952 2.408 47.976 ;
     RECT  0.06 47.976 2.408 48.096 ;
     RECT  0.084 48.096 2.408 48.12 ;
     RECT  0.06 48.12 2.408 48.24 ;
     RECT  0.084 48.24 2.408 48.264 ;
     RECT  0.06 48.264 2.408 48.384 ;
     RECT  0.084 48.384 2.408 48.408 ;
     RECT  0.06 48.408 2.408 48.528 ;
     RECT  0.084 48.528 2.408 48.552 ;
     RECT  0.06 48.552 2.408 48.672 ;
     RECT  0.084 48.672 2.408 48.696 ;
     RECT  0.06 48.696 2.408 48.816 ;
     RECT  0.084 48.816 2.408 48.84 ;
     RECT  0.06 48.84 2.408 48.96 ;
     RECT  0.084 48.96 2.408 48.984 ;
     RECT  0.06 48.984 2.408 49.104 ;
     RECT  0.084 49.104 2.408 49.128 ;
     RECT  0.06 49.128 2.408 49.248 ;
     RECT  0.084 49.248 2.408 49.272 ;
     RECT  0.06 49.272 2.408 49.392 ;
     RECT  0.084 49.392 2.408 49.416 ;
     RECT  0.06 49.416 2.408 49.536 ;
     RECT  0.084 49.536 2.408 49.56 ;
     RECT  2.408 2.148 2.512 105.852 ;
     RECT  2.512 2.418 2.704 105.582 ;
     RECT  2.704 47.088 5.497 49.56 ;
     RECT  5.497 47.088 5.747 49.704 ;
     RECT  5.747 47.088 5.977 49.224 ;
     RECT  5.893 39.024 7.808 39.048 ;
     RECT  5.977 47.088 7.808 47.736 ;
     RECT  5.977 49.008 7.808 49.224 ;
     RECT  7.808 2.148 7.912 105.852 ;
     RECT  7.912 2.418 8.104 105.582 ;
     RECT  8.104 47.088 8.237 47.736 ;
     RECT  8.237 47.088 10.837 47.112 ;
     RECT  10.837 46.272 10.883 47.112 ;
     RECT  10.883 46.272 10.979 46.296 ;
     RECT  8.104 39.024 13.208 39.048 ;
     RECT  10.933 43.056 13.208 43.08 ;
     RECT  12.517 45.216 13.208 45.24 ;
     RECT  12.373 46.224 13.208 46.248 ;
     RECT  13.208 2.148 13.312 105.852 ;
     RECT  13.312 2.418 13.504 105.582 ;
     RECT  13.504 39.024 18.608 39.048 ;
     RECT  13.504 43.056 18.608 43.08 ;
     RECT  13.504 45.216 18.608 45.24 ;
     RECT  18.608 2.148 18.712 105.852 ;
     RECT  18.712 2.418 18.904 105.582 ;
     RECT  18.904 45.216 21.665 45.24 ;
     RECT  23.173 45.024 23.317 45.048 ;
     RECT  18.904 39.024 24.008 39.048 ;
     RECT  18.904 43.056 24.008 43.08 ;
     RECT  23.317 44.112 24.008 45.048 ;
     RECT  24.008 2.148 24.112 105.852 ;
     RECT  24.112 2.418 24.304 105.582 ;
     RECT  24.304 39.024 29.408 39.048 ;
     RECT  24.304 43.056 29.408 43.08 ;
     RECT  24.304 44.112 29.408 44.136 ;
     RECT  29.408 2.148 29.512 105.852 ;
     RECT  29.512 2.418 29.704 105.582 ;
     RECT  29.704 44.112 32.465 44.136 ;
     RECT  29.704 43.056 33.973 43.08 ;
     RECT  29.704 39.024 34.808 39.048 ;
     RECT  33.973 40.896 34.808 40.92 ;
     RECT  33.973 43.056 34.808 43.944 ;
     RECT  34.808 2.148 34.912 105.852 ;
     RECT  34.912 2.418 35.104 105.582 ;
     RECT  35.104 105.456 36.421 105.48 ;
     RECT  36.421 105.456 36.853 105.816 ;
     RECT  36.853 105.456 37.043 106.008 ;
     RECT  35.104 104.304 38.051 104.328 ;
     RECT  37.043 105.456 38.149 105.48 ;
     RECT  37.933 103.2 39.121 103.224 ;
     RECT  39.121 102.576 39.205 103.224 ;
     RECT  38.149 104.64 39.301 105.48 ;
     RECT  35.104 43.056 39.445 43.08 ;
     RECT  39.301 104.64 39.589 106.056 ;
     RECT  39.409 51.168 39.697 51.192 ;
     RECT  39.805 48.96 39.841 48.984 ;
     RECT  39.877 107.808 40.019 107.832 ;
     RECT  39.205 103.2 40.021 103.224 ;
     RECT  39.445 54.72 40.069 54.744 ;
     RECT  39.877 44.16 40.165 44.184 ;
     RECT  39.697 50.88 40.165 51.192 ;
     RECT  35.104 39.024 40.208 39.048 ;
     RECT  35.104 40.896 40.208 40.92 ;
     RECT  39.445 42.48 40.208 43.08 ;
     RECT  40.165 44.16 40.208 44.376 ;
     RECT  39.769 45.744 40.208 45.768 ;
     RECT  39.841 48.72 40.208 48.984 ;
     RECT  40.165 50.88 40.208 51.768 ;
     RECT  39.517 52.992 40.208 53.016 ;
     RECT  40.069 54.72 40.208 55.704 ;
     RECT  40.021 103.2 40.208 103.32 ;
     RECT  39.589 104.304 40.208 106.056 ;
     RECT  40.208 2.148 40.312 106.056 ;
     RECT  40.312 2.418 40.504 106.056 ;
     RECT  40.504 103.2 40.645 104.904 ;
     RECT  40.504 106.032 40.673 106.056 ;
     RECT  40.645 104.352 40.835 104.904 ;
     RECT  40.645 103.2 40.853 103.32 ;
     RECT  40.835 104.352 41.293 104.376 ;
     RECT  40.504 50.592 41.497 53.304 ;
     RECT  41.497 50.592 41.533 53.688 ;
     RECT  40.504 38.688 41.749 40.92 ;
     RECT  40.504 42.192 41.749 43.08 ;
     RECT  40.504 48.72 41.821 48.984 ;
     RECT  41.821 48.72 41.845 49.272 ;
     RECT  41.533 50.592 41.845 53.976 ;
     RECT  40.504 44.16 41.893 47.448 ;
     RECT  41.845 48.72 41.893 53.976 ;
     RECT  41.749 38.688 42.325 43.08 ;
     RECT  42.325 38.688 42.853 43.176 ;
     RECT  41.893 44.16 42.853 53.976 ;
     RECT  42.853 38.688 43.272 53.976 ;
     RECT  43.272 38.688 45.608 70.776 ;
     RECT  40.853 103.2 45.608 103.224 ;
     RECT  45.608 2.148 45.712 70.776 ;
     RECT  45.608 72.888 45.712 105.852 ;
     RECT  45.712 2.418 45.904 70.776 ;
     RECT  45.712 73.158 45.904 105.582 ;
     RECT  45.904 38.688 51.008 70.776 ;
     RECT  45.904 103.2 51.008 103.224 ;
     RECT  51.008 2.148 51.112 70.776 ;
     RECT  51.008 72.888 51.112 105.852 ;
     RECT  51.112 2.418 51.304 70.776 ;
     RECT  51.112 73.158 51.304 105.582 ;
     RECT  55.477 30.864 56.408 30.888 ;
     RECT  51.304 38.688 56.408 70.776 ;
     RECT  51.304 103.2 56.408 103.224 ;
     RECT  56.408 2.148 56.512 70.776 ;
     RECT  56.408 72.888 56.512 105.852 ;
     RECT  56.512 2.418 56.704 70.776 ;
     RECT  56.512 73.158 56.704 105.582 ;
     RECT  56.704 30.864 61.808 30.888 ;
     RECT  56.704 38.688 61.808 70.776 ;
     RECT  56.704 103.2 61.808 103.224 ;
     RECT  61.808 2.148 61.912 70.776 ;
     RECT  61.808 72.888 61.912 105.852 ;
     RECT  61.912 2.418 62.104 70.776 ;
     RECT  61.912 73.158 62.104 105.582 ;
     RECT  62.104 30.864 66.089 30.888 ;
     RECT  66.373 31.296 67.208 31.32 ;
     RECT  62.104 38.688 67.208 70.776 ;
     RECT  62.104 103.2 67.208 103.224 ;
     RECT  67.208 2.148 67.312 70.776 ;
     RECT  67.208 72.888 67.312 105.852 ;
     RECT  67.312 2.418 67.504 70.776 ;
     RECT  67.312 73.158 67.504 105.582 ;
     RECT  67.504 38.688 72.608 70.776 ;
     RECT  67.504 103.2 72.608 103.224 ;
     RECT  72.608 2.148 72.712 70.776 ;
     RECT  72.608 72.888 72.712 105.852 ;
     RECT  72.712 2.418 72.904 70.776 ;
     RECT  72.712 73.158 72.904 105.582 ;
     RECT  72.904 38.688 76.848 70.776 ;
     RECT  76.741 1.728 76.885 1.752 ;
     RECT  76.021 3.696 76.997 3.72 ;
     RECT  76.848 43.968 77.033 53.976 ;
     RECT  77.033 44.064 77.069 53.976 ;
     RECT  76.489 0.096 77.075 0.12 ;
     RECT  77.173 2.88 77.353 2.904 ;
     RECT  76.885 1.248 77.461 1.752 ;
     RECT  77.461 1.152 77.533 1.752 ;
     RECT  77.533 1.104 77.795 1.752 ;
     RECT  77.795 1.152 77.86 1.752 ;
     RECT  77.86 1.152 78.008 1.8 ;
     RECT  77.353 2.832 78.008 2.904 ;
     RECT  77.173 5.184 78.008 5.208 ;
     RECT  76.848 38.688 78.008 42.888 ;
     RECT  72.904 103.2 78.008 103.224 ;
     RECT  78.008 72.888 78.112 105.852 ;
     RECT  78.008 1.152 78.304 42.888 ;
     RECT  78.112 73.158 78.304 105.582 ;
     RECT  78.304 1.152 78.545 3.096 ;
     RECT  78.545 1.152 78.797 1.848 ;
     RECT  78.545 2.88 78.949 3.096 ;
     RECT  78.797 1.248 79.093 1.848 ;
     RECT  77.069 44.16 79.157 53.976 ;
     RECT  79.157 51.936 79.445 53.976 ;
     RECT  78.949 3.072 79.469 3.096 ;
     RECT  79.469 3.072 79.553 3.432 ;
     RECT  79.621 105.792 79.724 105.816 ;
     RECT  79.093 1.248 79.765 1.752 ;
     RECT  79.724 104.832 79.81 105.816 ;
     RECT  79.157 44.16 79.985 50.904 ;
     RECT  79.553 3.072 80.053 3.336 ;
     RECT  79.445 52.224 80.057 53.976 ;
     RECT  80.057 52.608 80.093 53.976 ;
     RECT  78.304 5.184 80.269 5.208 ;
     RECT  80.093 52.608 80.273 53.88 ;
     RECT  79.765 1.152 80.309 1.752 ;
     RECT  79.81 104.784 80.341 105.816 ;
     RECT  80.269 5.184 80.377 5.4 ;
     RECT  80.273 52.608 80.381 53.592 ;
     RECT  80.341 104.784 80.485 106.056 ;
     RECT  79.985 45.216 80.489 50.904 ;
     RECT  80.381 53.376 80.489 53.592 ;
     RECT  80.489 45.408 80.525 50.904 ;
     RECT  80.377 5.136 80.531 5.4 ;
     RECT  80.485 104.784 80.588 106.104 ;
     RECT  79.945 107.184 80.819 107.208 ;
     RECT  80.525 45.504 80.885 50.904 ;
     RECT  80.489 53.568 80.885 53.592 ;
     RECT  80.701 0.096 80.963 0.12 ;
     RECT  80.309 1.152 80.989 1.176 ;
     RECT  80.531 5.184 80.993 5.4 ;
     RECT  80.588 104.304 81.029 106.104 ;
     RECT  80.989 1.056 81.107 1.176 ;
     RECT  80.053 2.88 81.205 3.336 ;
     RECT  81.205 2.88 81.241 3.432 ;
     RECT  81.029 104.304 81.251 106.008 ;
     RECT  78.304 103.2 81.253 103.224 ;
     RECT  81.251 104.304 81.253 104.328 ;
     RECT  81.253 103.008 81.34 104.328 ;
     RECT  81.241 2.256 81.349 3.432 ;
     RECT  81.349 1.632 81.353 3.432 ;
     RECT  81.353 1.632 81.539 2.904 ;
     RECT  81.539 1.728 81.683 2.904 ;
     RECT  81.683 2.88 81.827 2.904 ;
     RECT  80.885 45.888 81.893 50.904 ;
     RECT  81.251 105.456 81.973 106.008 ;
     RECT  82.033 107.184 82.259 107.208 ;
     RECT  81.893 46.944 82.645 50.904 ;
     RECT  81.34 104.304 82.681 104.328 ;
     RECT  81.973 105.456 82.681 105.816 ;
     RECT  82.349 2.928 82.789 2.952 ;
     RECT  81.34 103.008 82.933 103.032 ;
     RECT  82.681 104.304 83.269 105.816 ;
     RECT  81.683 1.728 83.408 1.896 ;
     RECT  82.789 2.88 83.408 2.952 ;
     RECT  80.993 5.184 83.408 5.208 ;
     RECT  78.304 38.688 83.408 42.888 ;
     RECT  79.985 44.16 83.408 44.184 ;
     RECT  82.645 46.944 83.408 51.144 ;
     RECT  82.933 103.008 83.408 103.224 ;
     RECT  83.269 104.304 83.408 106.008 ;
     RECT  83.269 0.144 83.555 0.168 ;
     RECT  83.408 1.728 83.704 106.008 ;
     RECT  83.704 104.64 83.765 106.008 ;
     RECT  83.765 104.64 83.801 105.864 ;
     RECT  83.704 2.88 83.837 3.096 ;
     RECT  83.704 103.008 83.981 103.224 ;
     RECT  83.704 5.184 84.197 5.208 ;
     RECT  83.801 105.456 84.197 105.864 ;
     RECT  84.197 105.456 84.341 105.48 ;
     RECT  83.704 47.328 84.413 47.736 ;
     RECT  84.413 47.712 84.449 47.736 ;
     RECT  83.981 103.2 84.521 103.224 ;
     RECT  83.704 49.248 84.593 51.144 ;
     RECT  83.704 1.728 84.629 1.8 ;
     RECT  84.629 1.728 84.805 1.752 ;
     RECT  84.593 49.824 85.241 51.144 ;
     RECT  83.837 2.88 85.285 2.904 ;
     RECT  85.241 50.88 85.529 51.144 ;
     RECT  85.529 51.12 85.565 51.144 ;
     RECT  84.805 1.152 85.669 1.752 ;
     RECT  85.241 49.824 85.673 49.848 ;
     RECT  85.669 1.152 85.709 1.8 ;
     RECT  85.709 1.728 85.961 1.8 ;
     RECT  85.961 1.776 86.033 1.8 ;
     RECT  83.704 38.688 88.808 42.888 ;
     RECT  83.704 44.16 88.808 44.184 ;
     RECT  88.808 2.148 88.912 105.852 ;
     RECT  88.912 2.418 89.104 105.582 ;
     RECT  89.104 38.688 94.208 42.888 ;
     RECT  89.104 44.16 94.208 44.184 ;
     RECT  94.208 2.148 94.312 105.852 ;
     RECT  94.312 2.418 94.504 105.582 ;
     RECT  99.061 50.112 99.157 50.136 ;
     RECT  98.953 51.36 99.157 51.384 ;
     RECT  94.504 44.16 99.349 44.184 ;
     RECT  94.504 38.688 99.608 42.888 ;
     RECT  99.349 44.16 99.608 44.472 ;
     RECT  99.025 46.32 99.608 46.344 ;
     RECT  98.737 47.856 99.608 47.88 ;
     RECT  99.157 50.112 99.608 51.912 ;
     RECT  99.608 2.148 99.712 105.852 ;
     RECT  99.712 2.418 99.904 105.582 ;
     RECT  99.904 50.64 100.037 50.664 ;
     RECT  99.904 46.32 100.217 46.344 ;
     RECT  99.904 44.16 100.897 44.472 ;
     RECT  99.904 47.76 100.931 48.456 ;
     RECT  100.897 44.064 100.937 44.472 ;
     RECT  99.904 38.688 101.081 42.888 ;
     RECT  100.931 48.432 101.117 48.456 ;
     RECT  100.885 50.16 101.369 50.184 ;
     RECT  101.081 38.736 102.085 42.888 ;
     RECT  100.937 44.064 102.085 44.184 ;
     RECT  102.085 38.736 102.125 44.184 ;
     RECT  102.125 38.736 102.269 43.368 ;
     RECT  102.284 47.856 102.309 47.88 ;
     RECT  102.309 47.856 102.371 48.456 ;
     RECT  102.269 42.864 102.665 43.368 ;
     RECT  102.269 38.736 102.845 41.736 ;
     RECT  102.877 50.736 103.093 50.76 ;
     RECT  103.052 51.792 103.093 51.816 ;
     RECT  103.093 50.736 103.139 52.488 ;
     RECT  102.845 41.376 103.241 41.736 ;
     RECT  102.371 48.432 103.673 48.456 ;
     RECT  103.139 52.464 103.673 52.488 ;
     RECT  102.373 44.832 103.745 44.856 ;
     RECT  102.845 38.736 103.853 40.392 ;
     RECT  103.241 41.376 103.889 41.544 ;
     RECT  103.853 39.312 103.925 40.392 ;
     RECT  103.889 41.376 103.961 41.4 ;
     RECT  103.925 39.312 103.997 39.864 ;
     RECT  102.665 42.864 104.033 42.888 ;
     RECT  103.997 39.312 105.008 39.336 ;
     RECT  103.139 50.976 105.008 51 ;
     RECT  105.008 2.148 105.112 105.852 ;
     RECT  105.112 2.418 105.304 105.582 ;
     RECT  105.304 46.512 106.513 47.688 ;
     RECT  105.304 43.632 106.549 43.656 ;
     RECT  105.304 44.64 106.549 44.808 ;
     RECT  106.513 46.368 106.549 47.688 ;
     RECT  105.304 48.816 106.549 49.272 ;
     RECT  105.304 50.4 106.549 52.296 ;
     RECT  106.549 43.488 106.585 43.656 ;
     RECT  106.549 44.64 106.585 47.688 ;
     RECT  106.549 48.672 106.585 52.296 ;
     RECT  106.585 43.344 107.161 52.296 ;
     RECT  107.161 43.344 107.916 43.368 ;
     RECT  107.161 43.368 107.964 43.488 ;
     RECT  107.161 43.488 107.916 43.512 ;
     RECT  107.161 43.512 107.964 43.632 ;
     RECT  107.161 43.632 107.916 43.656 ;
     RECT  107.161 43.656 107.964 43.776 ;
     RECT  107.161 43.776 107.916 43.8 ;
     RECT  107.161 43.8 107.964 43.92 ;
     RECT  107.161 43.92 107.916 43.944 ;
     RECT  107.161 43.944 107.964 44.064 ;
     RECT  107.161 44.064 107.916 44.088 ;
     RECT  107.161 44.088 107.964 44.208 ;
     RECT  107.161 44.208 107.916 44.232 ;
     RECT  107.161 44.232 107.964 44.352 ;
     RECT  107.161 44.352 107.916 44.376 ;
     RECT  107.161 44.376 107.964 44.496 ;
     RECT  107.161 44.496 107.916 44.52 ;
     RECT  107.161 44.52 107.964 44.64 ;
     RECT  107.161 44.64 107.916 44.664 ;
     RECT  107.161 44.664 107.964 44.784 ;
     RECT  107.161 44.784 107.916 44.808 ;
     RECT  107.161 44.808 107.964 44.928 ;
     RECT  107.161 44.928 107.916 44.952 ;
     RECT  107.161 44.952 107.964 45.072 ;
     RECT  107.161 45.072 107.916 45.096 ;
     RECT  107.161 45.096 107.964 45.216 ;
     RECT  107.161 45.216 107.916 45.24 ;
     RECT  107.161 45.24 107.964 45.36 ;
     RECT  107.161 45.36 107.916 45.384 ;
     RECT  107.161 45.384 107.964 45.504 ;
     RECT  107.161 45.504 107.916 45.528 ;
     RECT  107.161 45.528 107.964 45.648 ;
     RECT  107.161 45.648 107.916 45.672 ;
     RECT  107.161 45.672 107.964 45.792 ;
     RECT  107.161 45.792 107.916 45.816 ;
     RECT  107.161 45.816 107.964 45.936 ;
     RECT  107.161 45.936 107.916 45.96 ;
     RECT  107.161 45.96 107.964 46.08 ;
     RECT  107.161 46.08 107.916 46.104 ;
     RECT  107.161 46.104 107.964 46.224 ;
     RECT  107.161 46.224 107.916 46.248 ;
     RECT  107.161 46.248 107.964 46.368 ;
     RECT  107.161 46.368 107.916 46.392 ;
     RECT  107.161 46.392 107.964 46.512 ;
     RECT  107.161 46.512 107.916 46.536 ;
     RECT  107.161 46.536 107.964 46.656 ;
     RECT  107.161 46.656 107.916 46.68 ;
     RECT  107.161 46.68 107.964 46.8 ;
     RECT  107.161 46.8 107.916 46.824 ;
     RECT  107.161 46.824 107.964 46.944 ;
     RECT  107.161 46.944 107.916 46.968 ;
     RECT  107.161 46.968 107.964 47.088 ;
     RECT  107.161 47.088 107.916 47.112 ;
     RECT  107.161 47.112 107.964 47.232 ;
     RECT  107.161 47.232 107.916 47.256 ;
     RECT  107.161 47.256 107.964 47.376 ;
     RECT  107.161 47.376 107.916 47.4 ;
     RECT  107.161 47.4 107.964 47.52 ;
     RECT  107.161 47.52 107.916 47.544 ;
     RECT  107.161 47.544 107.964 47.664 ;
     RECT  107.161 47.664 107.916 47.688 ;
     RECT  107.161 47.688 107.964 47.808 ;
     RECT  107.161 47.808 107.916 47.832 ;
     RECT  107.161 47.832 107.964 47.952 ;
     RECT  107.161 47.952 107.916 47.976 ;
     RECT  107.161 47.976 107.964 48.096 ;
     RECT  107.161 48.096 107.916 48.12 ;
     RECT  107.161 48.12 107.964 48.24 ;
     RECT  107.161 48.24 107.916 48.264 ;
     RECT  107.161 48.264 107.964 48.384 ;
     RECT  107.161 48.384 107.916 48.408 ;
     RECT  107.161 48.408 107.964 48.528 ;
     RECT  107.161 48.528 107.916 48.552 ;
     RECT  107.161 48.552 107.964 48.672 ;
     RECT  107.161 48.672 107.916 48.696 ;
     RECT  107.161 48.696 107.964 48.816 ;
     RECT  107.161 48.816 107.916 48.84 ;
     RECT  107.161 48.84 107.964 48.96 ;
     RECT  107.161 48.96 107.916 48.984 ;
     RECT  107.161 48.984 107.964 49.104 ;
     RECT  107.161 49.104 107.916 49.128 ;
     RECT  107.161 49.128 107.964 49.248 ;
     RECT  107.161 49.248 107.916 49.272 ;
     RECT  107.161 49.272 107.964 49.392 ;
     RECT  107.161 49.392 107.916 49.416 ;
     RECT  107.161 49.416 107.964 49.536 ;
     RECT  107.161 49.536 107.916 49.56 ;
     RECT  107.161 49.56 107.964 49.68 ;
     RECT  107.161 49.68 107.916 49.704 ;
     RECT  107.161 49.704 107.964 49.824 ;
     RECT  107.161 49.824 107.916 49.848 ;
     RECT  107.161 49.848 107.964 49.968 ;
     RECT  107.161 49.968 107.916 49.992 ;
     RECT  107.161 49.992 107.964 50.112 ;
     RECT  107.161 50.112 107.916 50.136 ;
     RECT  107.161 50.136 107.964 50.256 ;
     RECT  107.161 50.256 107.916 50.28 ;
     RECT  107.161 50.28 107.964 50.4 ;
     RECT  107.161 50.4 107.916 50.424 ;
     RECT  107.161 50.424 107.964 50.544 ;
     RECT  107.161 50.544 107.916 50.568 ;
     RECT  107.161 50.568 107.964 50.688 ;
     RECT  107.161 50.688 107.916 50.712 ;
     RECT  107.161 50.712 107.964 50.832 ;
     RECT  107.161 50.832 107.916 50.856 ;
     RECT  107.161 50.856 107.964 50.976 ;
     RECT  107.161 50.976 107.916 51 ;
     RECT  107.161 51 107.964 51.12 ;
     RECT  107.161 51.12 107.916 51.144 ;
     RECT  107.161 51.144 107.964 51.264 ;
     RECT  107.161 51.264 107.916 51.288 ;
     RECT  107.161 51.288 107.964 51.408 ;
     RECT  107.161 51.408 107.916 51.432 ;
     RECT  107.161 51.432 107.964 51.552 ;
     RECT  107.161 51.552 107.916 51.576 ;
     RECT  107.161 51.576 107.964 51.696 ;
     RECT  107.161 51.696 107.916 51.72 ;
     RECT  107.161 51.72 107.964 51.84 ;
     RECT  107.161 51.84 107.916 51.864 ;
     RECT  107.161 51.864 107.964 51.984 ;
     RECT  107.161 51.984 107.916 52.008 ;
     RECT  107.161 52.008 107.964 52.128 ;
     RECT  107.161 52.128 107.916 52.152 ;
     RECT  107.161 52.152 107.964 52.272 ;
     RECT  107.161 52.272 107.916 52.296 ;
     RECT  107.161 52.296 107.964 52.416 ;
     RECT  107.161 52.416 107.916 52.44 ;
    LAYER M5 ;
     RECT  76.776 0.016 76.896 0.084 ;
     RECT  76.92 0.016 77.04 0.084 ;
     RECT  77.064 0.016 77.184 0.084 ;
     RECT  77.208 0.016 77.328 0.084 ;
     RECT  77.352 0.016 77.472 0.084 ;
     RECT  77.496 0.016 77.616 0.084 ;
     RECT  77.64 0.016 77.76 0.084 ;
     RECT  77.784 0.016 77.904 0.084 ;
     RECT  77.928 0.016 78.048 0.084 ;
     RECT  78.072 0.016 78.192 0.084 ;
     RECT  78.216 0.016 78.336 0.084 ;
     RECT  78.36 0.016 78.48 0.084 ;
     RECT  78.504 0.016 78.624 0.084 ;
     RECT  78.648 0.016 78.768 0.084 ;
     RECT  78.792 0.016 78.912 0.084 ;
     RECT  78.936 0.016 79.056 0.084 ;
     RECT  79.08 0.016 79.2 0.084 ;
     RECT  79.224 0.016 79.344 0.084 ;
     RECT  79.368 0.016 79.488 0.084 ;
     RECT  79.512 0.016 79.632 0.084 ;
     RECT  79.656 0.016 79.776 0.084 ;
     RECT  79.8 0.016 79.92 0.084 ;
     RECT  79.944 0.016 80.064 0.084 ;
     RECT  80.088 0.016 80.208 0.084 ;
     RECT  80.232 0.016 80.352 0.084 ;
     RECT  80.376 0.016 80.496 0.084 ;
     RECT  80.52 0.016 80.64 0.084 ;
     RECT  80.664 0.016 80.784 0.084 ;
     RECT  80.808 0.016 80.928 0.084 ;
     RECT  80.952 0.016 81.072 0.084 ;
     RECT  81.096 0.016 81.216 0.084 ;
     RECT  81.24 0.016 81.36 0.084 ;
     RECT  81.384 0.016 81.504 0.084 ;
     RECT  81.528 0.016 81.648 0.084 ;
     RECT  81.672 0.016 81.792 0.084 ;
     RECT  81.816 0.016 81.936 0.084 ;
     RECT  81.96 0.016 82.08 0.084 ;
     RECT  82.104 0.016 82.224 0.084 ;
     RECT  82.248 0.016 82.368 0.084 ;
     RECT  82.392 0.016 82.512 0.084 ;
     RECT  82.536 0.016 82.656 0.084 ;
     RECT  82.68 0.016 82.8 0.084 ;
     RECT  82.824 0.016 82.944 0.084 ;
     RECT  82.968 0.016 83.088 0.084 ;
     RECT  83.112 0.016 83.232 0.084 ;
     RECT  83.256 0.016 83.376 0.084 ;
     RECT  83.4 0.016 83.52 0.084 ;
     RECT  83.544 0.016 83.664 0.084 ;
     RECT  83.688 0.016 83.808 0.084 ;
     RECT  83.832 0.016 83.952 0.084 ;
     RECT  83.976 0.016 84.096 0.084 ;
     RECT  84.12 0.016 84.24 0.084 ;
     RECT  84.264 0.016 84.384 0.084 ;
     RECT  84.408 0.016 84.528 0.084 ;
     RECT  84.552 0.016 84.672 0.084 ;
     RECT  84.696 0.016 84.816 0.084 ;
     RECT  84.84 0.016 84.96 0.084 ;
     RECT  84.984 0.016 85.104 0.084 ;
     RECT  85.128 0.016 85.248 0.084 ;
     RECT  85.272 0.016 85.392 0.084 ;
     RECT  85.416 0.016 85.536 0.084 ;
     RECT  85.56 0.016 85.68 0.084 ;
     RECT  85.704 0.016 85.824 0.084 ;
     RECT  76.752 0.084 85.848 1.763 ;
     RECT  77.184 1.763 85.704 1.811 ;
     RECT  2.4 2.137 2.52 2.151 ;
     RECT  7.8 2.137 7.92 2.151 ;
     RECT  13.2 2.137 13.32 2.151 ;
     RECT  18.6 2.137 18.72 2.151 ;
     RECT  24 2.137 24.12 2.151 ;
     RECT  29.4 2.137 29.52 2.151 ;
     RECT  34.8 2.137 34.92 2.151 ;
     RECT  40.2 2.137 40.32 2.151 ;
     RECT  45.6 2.137 45.72 2.151 ;
     RECT  51 2.137 51.12 2.151 ;
     RECT  56.4 2.137 56.52 2.151 ;
     RECT  61.8 2.137 61.92 2.151 ;
     RECT  67.2 2.137 67.32 2.151 ;
     RECT  72.6 2.137 72.72 2.151 ;
     RECT  88.8 2.137 88.92 2.151 ;
     RECT  94.2 2.137 94.32 2.151 ;
     RECT  99.6 2.137 99.72 2.151 ;
     RECT  105 2.137 105.12 2.151 ;
     RECT  77.184 1.811 85.272 2.915 ;
     RECT  82.368 2.915 83.712 2.963 ;
     RECT  79.344 2.915 81.24 3.107 ;
     RECT  79.488 3.107 81.24 3.347 ;
     RECT  79.488 3.347 79.512 3.443 ;
     RECT  80.496 3.347 81.24 3.443 ;
     RECT  80.496 3.443 80.52 5.171 ;
     RECT  77.376 2.915 78.312 5.173 ;
     RECT  56.4 2.151 56.712 30.853 ;
     RECT  67.2 2.151 67.512 31.285 ;
     RECT  40.2 2.151 40.512 38.677 ;
     RECT  40.2 38.677 40.92 38.725 ;
     RECT  66.384 31.285 67.512 39.059 ;
     RECT  40.2 38.725 41.592 39.301 ;
     RECT  40.2 39.301 41.88 40.357 ;
     RECT  40.2 40.357 42.264 40.405 ;
     RECT  55.488 30.853 56.712 40.645 ;
     RECT  55.392 40.645 56.712 40.691 ;
     RECT  34.8 2.151 35.112 40.885 ;
     RECT  86.64 41.749 86.76 41.891 ;
     RECT  86.736 41.891 86.76 41.987 ;
     RECT  40.2 40.405 42.936 42.325 ;
     RECT  77.184 5.173 78.312 42.373 ;
     RECT  40.2 42.325 43.032 42.469 ;
     RECT  55.392 40.691 55.416 42.515 ;
     RECT  33.984 40.885 35.112 43.955 ;
     RECT  24 2.151 24.312 44.101 ;
     RECT  76.992 42.373 78.312 44.195 ;
     RECT  76.992 44.195 77.016 44.387 ;
     RECT  39.456 42.469 43.032 44.437 ;
     RECT  39.456 44.437 43.08 44.677 ;
     RECT  23.328 44.101 24.312 45.059 ;
     RECT  13.2 2.151 13.512 45.205 ;
     RECT  12.528 45.205 13.512 46.259 ;
     RECT  10.944 43.045 10.968 46.261 ;
     RECT  10.848 46.261 10.968 46.307 ;
     RECT  10.848 46.307 10.872 47.123 ;
     RECT  102.336 47.845 102.36 48.467 ;
     RECT  5.904 39.013 5.928 48.515 ;
     RECT  5.712 48.853 5.736 49.715 ;
     RECT  99.6 2.151 99.912 50.101 ;
     RECT  100.896 44.149 100.92 50.195 ;
     RECT  39.456 44.677 43.128 50.723 ;
     RECT  43.104 50.723 43.128 50.819 ;
     RECT  83.4 2.963 83.712 50.869 ;
     RECT  82.656 50.869 83.712 51.155 ;
     RECT  99.168 50.101 99.912 51.923 ;
     RECT  103.104 50.725 103.128 52.499 ;
     RECT  39.456 50.723 41.256 54.755 ;
     RECT  40.08 54.755 41.256 102.565 ;
     RECT  39.168 102.565 41.256 103.331 ;
     RECT  39.168 103.331 39.192 104.293 ;
     RECT  40.2 103.331 41.256 104.293 ;
     RECT  81.264 102.997 81.288 104.293 ;
     RECT  39.168 104.293 41.256 104.387 ;
     RECT  36.288 104.293 38.04 104.629 ;
     RECT  39.168 104.387 40.824 104.629 ;
     RECT  80.64 104.293 82.392 104.629 ;
     RECT  83.4 51.155 83.712 104.629 ;
     RECT  80.64 104.629 83.712 104.773 ;
     RECT  80.064 104.773 83.712 104.821 ;
     RECT  36.288 104.629 40.824 104.915 ;
     RECT  34.8 43.955 35.112 105.445 ;
     RECT  36.288 104.915 40.512 105.445 ;
     RECT  79.776 104.821 83.712 105.445 ;
     RECT  79.776 105.445 84.12 105.781 ;
     RECT  2.4 2.151 2.712 105.849 ;
     RECT  7.8 2.151 8.112 105.849 ;
     RECT  13.2 46.259 13.512 105.849 ;
     RECT  18.6 2.151 18.912 105.849 ;
     RECT  24 45.059 24.312 105.849 ;
     RECT  29.4 2.151 29.712 105.849 ;
     RECT  34.8 105.445 40.512 105.849 ;
     RECT  45.6 2.151 45.912 105.849 ;
     RECT  51 2.151 51.312 105.849 ;
     RECT  56.4 40.691 56.712 105.849 ;
     RECT  61.8 2.151 62.112 105.849 ;
     RECT  67.2 39.059 67.512 105.849 ;
     RECT  72.6 2.151 72.912 105.849 ;
     RECT  78 44.195 78.312 105.849 ;
     RECT  88.8 2.151 89.112 105.849 ;
     RECT  94.2 2.151 94.512 105.849 ;
     RECT  99.6 51.923 99.912 105.849 ;
     RECT  105 2.151 105.312 105.849 ;
     RECT  2.4 105.849 2.52 105.863 ;
     RECT  7.8 105.849 7.92 105.863 ;
     RECT  13.2 105.849 13.32 105.863 ;
     RECT  18.6 105.849 18.72 105.863 ;
     RECT  24 105.849 24.12 105.863 ;
     RECT  29.4 105.849 29.52 105.863 ;
     RECT  34.8 105.849 40.344 105.863 ;
     RECT  45.6 105.849 45.72 105.863 ;
     RECT  51 105.849 51.12 105.863 ;
     RECT  56.4 105.849 56.52 105.863 ;
     RECT  61.8 105.849 61.92 105.863 ;
     RECT  67.2 105.849 67.32 105.863 ;
     RECT  72.6 105.849 72.72 105.863 ;
     RECT  78 105.849 78.12 105.863 ;
     RECT  88.8 105.849 88.92 105.863 ;
     RECT  94.2 105.849 94.32 105.863 ;
     RECT  99.6 105.849 99.72 105.863 ;
     RECT  105 105.849 105.12 105.863 ;
     RECT  35.856 105.863 40.344 107.916 ;
     RECT  35.88 107.916 36 107.984 ;
     RECT  36.024 107.916 36.144 107.984 ;
     RECT  36.168 107.916 36.288 107.984 ;
     RECT  36.312 107.916 36.432 107.984 ;
     RECT  36.456 107.916 36.576 107.984 ;
     RECT  36.6 107.916 36.72 107.984 ;
     RECT  36.744 107.916 36.864 107.984 ;
     RECT  36.888 107.916 37.008 107.984 ;
     RECT  37.032 107.916 37.152 107.984 ;
     RECT  37.176 107.916 37.296 107.984 ;
     RECT  37.32 107.916 37.44 107.984 ;
     RECT  37.464 107.916 37.584 107.984 ;
     RECT  37.608 107.916 37.728 107.984 ;
     RECT  37.752 107.916 37.872 107.984 ;
     RECT  37.896 107.916 38.016 107.984 ;
     RECT  38.04 107.916 38.16 107.984 ;
     RECT  38.184 107.916 38.304 107.984 ;
     RECT  38.328 107.916 38.448 107.984 ;
     RECT  38.472 107.916 38.592 107.984 ;
     RECT  38.616 107.916 38.736 107.984 ;
     RECT  38.76 107.916 38.88 107.984 ;
     RECT  38.904 107.916 39.024 107.984 ;
     RECT  39.048 107.916 39.168 107.984 ;
     RECT  39.192 107.916 39.312 107.984 ;
     RECT  39.336 107.916 39.456 107.984 ;
     RECT  39.48 107.916 39.6 107.984 ;
     RECT  39.624 107.916 39.744 107.984 ;
     RECT  39.768 107.916 39.888 107.984 ;
     RECT  39.912 107.916 40.032 107.984 ;
     RECT  40.056 107.916 40.176 107.984 ;
     RECT  40.2 107.916 40.32 107.984 ;
     RECT  79.632 105.781 84.12 107.916 ;
     RECT  79.656 107.916 79.776 107.984 ;
     RECT  79.8 107.916 79.92 107.984 ;
     RECT  79.944 107.916 80.064 107.984 ;
     RECT  80.088 107.916 80.208 107.984 ;
     RECT  80.232 107.916 80.352 107.984 ;
     RECT  80.376 107.916 80.496 107.984 ;
     RECT  80.52 107.916 80.64 107.984 ;
     RECT  80.664 107.916 80.784 107.984 ;
     RECT  80.808 107.916 80.928 107.984 ;
     RECT  80.952 107.916 81.072 107.984 ;
     RECT  81.096 107.916 81.216 107.984 ;
     RECT  81.24 107.916 81.36 107.984 ;
     RECT  81.384 107.916 81.504 107.984 ;
     RECT  81.528 107.916 81.648 107.984 ;
     RECT  81.672 107.916 81.792 107.984 ;
     RECT  81.816 107.916 81.936 107.984 ;
     RECT  81.96 107.916 82.08 107.984 ;
     RECT  82.104 107.916 82.224 107.984 ;
     RECT  82.248 107.916 82.368 107.984 ;
     RECT  82.392 107.916 82.512 107.984 ;
     RECT  82.536 107.916 82.656 107.984 ;
     RECT  82.68 107.916 82.8 107.984 ;
     RECT  82.824 107.916 82.944 107.984 ;
     RECT  82.968 107.916 83.088 107.984 ;
     RECT  83.112 107.916 83.232 107.984 ;
     RECT  83.256 107.916 83.376 107.984 ;
     RECT  83.4 107.916 83.52 107.984 ;
     RECT  83.544 107.916 83.664 107.984 ;
     RECT  83.688 107.916 83.808 107.984 ;
     RECT  83.832 107.916 83.952 107.984 ;
     RECT  83.976 107.916 84.096 107.984 ;
     RECT  78.312 2.915 79.344 3.107 ;
     RECT  81.24 2.915 82.368 2.963 ;
     RECT  78.312 3.107 79.488 3.443 ;
     RECT  79.512 3.347 80.496 3.443 ;
     RECT  55.416 40.691 56.4 42.515 ;
     RECT  99.912 44.149 100.896 50.195 ;
     RECT  77.016 44.195 78 44.387 ;
     RECT  100.92 47.845 102.336 48.467 ;
     RECT  39.192 103.331 40.2 104.293 ;
     RECT  35.112 104.293 36.288 105.445 ;
     RECT  38.04 104.293 39.168 104.629 ;
     RECT  82.392 104.293 83.4 104.629 ;
     RECT  78.312 104.821 79.776 105.781 ;
     RECT  78.312 105.781 79.632 105.849 ;
     RECT  78.12 105.849 79.632 105.863 ;
  END
END ot_sram_escape128x64_1019
END LIBRARY
